VERSION 5.8 ;
BUSBITCHARS "[]" ;
DIVIDERCHAR "/" ;
UNITS
    DATABASE MICRONS 1000 ;
END UNITS

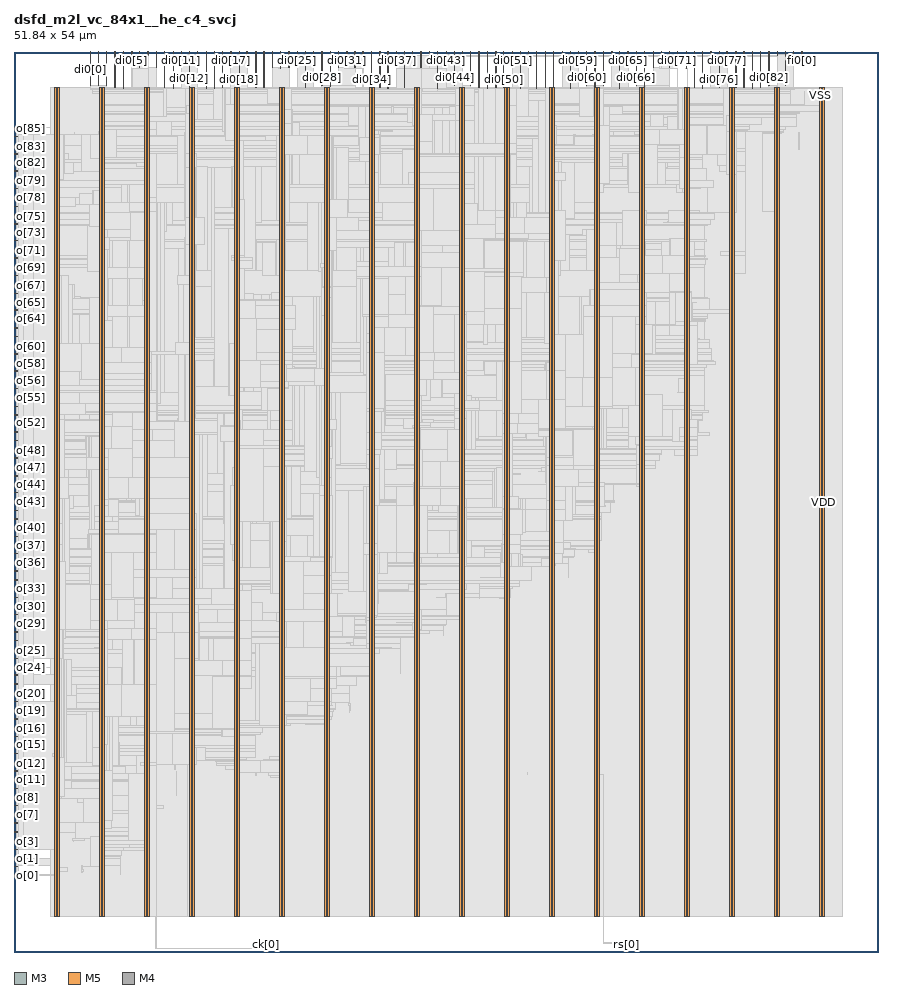
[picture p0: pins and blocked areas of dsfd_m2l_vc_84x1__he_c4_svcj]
MACRO dsfd_m2l_vc_84x1__he_c4_svcj
  FOREIGN dsfd_m2l_vc_84x1__he_c4_svcj 0 0 ;
  CLASS BLOCK ;
  SIZE 51.84 BY 54 ;
  PIN ck[0]
    DIRECTION INPUT ;
    USE SIGNAL ;
    PORT
      LAYER M3 ;
        RECT  15.12 0 15.138 0.144 ;
    END
    PORT
      LAYER M3 ;
        RECT  15.12 0.108 15.138 0.221 ;
    END
  END ck[0]
  PIN di0[0]
    DIRECTION INPUT ;
    USE SIGNAL ;
    PORT
      LAYER M3 ;
        RECT  4.572 53.856 4.59 54 ;
    END
    PORT
      LAYER M3 ;
        RECT  4.572 52.013 4.59 53.868 ;
    END
  END di0[0]
  PIN di0[10]
    DIRECTION INPUT ;
    USE SIGNAL ;
    PORT
      LAYER M3 ;
        RECT  9.54 53.856 9.558 54 ;
    END
    PORT
      LAYER M3 ;
        RECT  9.54 51.821 9.558 53.868 ;
    END
  END di0[10]
  PIN di0[11]
    DIRECTION INPUT ;
    USE SIGNAL ;
    PORT
      LAYER M5 ;
        RECT  10.032 53.808 10.056 54 ;
    END
  END di0[11]
  PIN di0[12]
    DIRECTION INPUT ;
    USE SIGNAL ;
    PORT
      LAYER M3 ;
        RECT  10.512 53.856 10.53 54 ;
    END
    PORT
      LAYER M3 ;
        RECT  10.512 51.935 10.53 53.868 ;
    END
  END di0[12]
  PIN di0[13]
    DIRECTION INPUT ;
    USE SIGNAL ;
    PORT
      LAYER M5 ;
        RECT  10.992 53.808 11.016 54 ;
    END
  END di0[13]
  PIN di0[14]
    DIRECTION INPUT ;
    USE SIGNAL ;
    PORT
      LAYER M3 ;
        RECT  11.52 53.856 11.538 54 ;
    END
    PORT
      LAYER M3 ;
        RECT  11.52 51.821 11.538 53.868 ;
    END
  END di0[14]
  PIN di0[15]
    DIRECTION INPUT ;
    USE SIGNAL ;
    PORT
      LAYER M5 ;
        RECT  12 53.808 12.024 54 ;
    END
    PORT
      LAYER M5 ;
        RECT  12 51.781 12.024 53.84 ;
    END
  END di0[15]
  PIN di0[16]
    DIRECTION INPUT ;
    USE SIGNAL ;
    PORT
      LAYER M3 ;
        RECT  12.492 53.856 12.51 54 ;
    END
    PORT
      LAYER M3 ;
        RECT  12.492 51.857 12.51 53.868 ;
    END
  END di0[16]
  PIN di0[17]
    DIRECTION INPUT ;
    USE SIGNAL ;
    PORT
      LAYER M5 ;
        RECT  13.008 53.808 13.032 54 ;
    END
  END di0[17]
  PIN di0[18]
    DIRECTION INPUT ;
    USE SIGNAL ;
    PORT
      LAYER M3 ;
        RECT  13.5 53.856 13.518 54 ;
    END
    PORT
      LAYER M3 ;
        RECT  13.5 51.869 13.518 53.868 ;
    END
  END di0[18]
  PIN di0[19]
    DIRECTION INPUT ;
    USE SIGNAL ;
    PORT
      LAYER M5 ;
        RECT  13.968 53.808 13.992 54 ;
    END
  END di0[19]
  PIN di0[1]
    DIRECTION INPUT ;
    USE SIGNAL ;
    PORT
      LAYER M5 ;
        RECT  5.04 53.808 5.064 54 ;
    END
    PORT
      LAYER M5 ;
        RECT  5.04 51.973 5.064 53.84 ;
    END
  END di0[1]
  PIN di0[20]
    DIRECTION INPUT ;
    USE SIGNAL ;
    PORT
      LAYER M3 ;
        RECT  14.508 53.856 14.526 54 ;
    END
    PORT
      LAYER M3 ;
        RECT  14.508 51.869 14.526 53.868 ;
    END
  END di0[20]
  PIN di0[21]
    DIRECTION INPUT ;
    USE SIGNAL ;
    PORT
      LAYER M5 ;
        RECT  14.976 53.808 15 54 ;
    END
    PORT
      LAYER M5 ;
        RECT  14.976 51.863 15 53.84 ;
    END
  END di0[21]
  PIN di0[22]
    DIRECTION INPUT ;
    USE SIGNAL ;
    PORT
      LAYER M3 ;
        RECT  15.48 53.856 15.498 54 ;
    END
    PORT
      LAYER M3 ;
        RECT  15.48 53.069 15.498 53.868 ;
    END
  END di0[22]
  PIN di0[23]
    DIRECTION INPUT ;
    USE SIGNAL ;
    PORT
      LAYER M5 ;
        RECT  15.984 53.808 16.008 54 ;
    END
    PORT
      LAYER M5 ;
        RECT  15.984 53.029 16.008 53.84 ;
    END
  END di0[23]
  PIN di0[24]
    DIRECTION INPUT ;
    USE SIGNAL ;
    PORT
      LAYER M3 ;
        RECT  16.488 53.856 16.506 54 ;
    END
    PORT
      LAYER M3 ;
        RECT  16.488 53.069 16.506 53.868 ;
    END
  END di0[24]
  PIN di0[25]
    DIRECTION INPUT ;
    USE SIGNAL ;
    PORT
      LAYER M5 ;
        RECT  16.992 53.808 17.016 54 ;
    END
  END di0[25]
  PIN di0[26]
    DIRECTION INPUT ;
    USE SIGNAL ;
    PORT
      LAYER M3 ;
        RECT  17.46 53.856 17.478 54 ;
    END
    PORT
      LAYER M3 ;
        RECT  17.46 51.869 17.478 53.868 ;
    END
  END di0[26]
  PIN di0[27]
    DIRECTION INPUT ;
    USE SIGNAL ;
    PORT
      LAYER M5 ;
        RECT  17.952 53.808 17.976 54 ;
    END
  END di0[27]
  PIN di0[28]
    DIRECTION INPUT ;
    USE SIGNAL ;
    PORT
      LAYER M3 ;
        RECT  18.468 53.856 18.486 54 ;
    END
    PORT
      LAYER M3 ;
        RECT  18.468 51.965 18.486 53.868 ;
    END
  END di0[28]
  PIN di0[29]
    DIRECTION INPUT ;
    USE SIGNAL ;
    PORT
      LAYER M5 ;
        RECT  18.96 53.808 18.984 54 ;
    END
    PORT
      LAYER M5 ;
        RECT  18.96 51.925 18.984 53.84 ;
    END
  END di0[29]
  PIN di0[2]
    DIRECTION INPUT ;
    USE SIGNAL ;
    PORT
      LAYER M3 ;
        RECT  5.544 53.856 5.562 54 ;
    END
    PORT
      LAYER M3 ;
        RECT  5.544 52.013 5.562 53.868 ;
    END
  END di0[2]
  PIN di0[30]
    DIRECTION INPUT ;
    USE SIGNAL ;
    PORT
      LAYER M3 ;
        RECT  19.44 53.856 19.458 54 ;
    END
    PORT
      LAYER M3 ;
        RECT  19.44 53.069 19.458 53.868 ;
    END
  END di0[30]
  PIN di0[31]
    DIRECTION INPUT ;
    USE SIGNAL ;
    PORT
      LAYER M5 ;
        RECT  19.968 53.808 19.992 54 ;
    END
  END di0[31]
  PIN di0[32]
    DIRECTION INPUT ;
    USE SIGNAL ;
    PORT
      LAYER M3 ;
        RECT  20.448 53.856 20.466 54 ;
    END
    PORT
      LAYER M3 ;
        RECT  20.448 53.069 20.466 53.868 ;
    END
  END di0[32]
  PIN di0[33]
    DIRECTION INPUT ;
    USE SIGNAL ;
    PORT
      LAYER M5 ;
        RECT  20.928 53.808 20.952 54 ;
    END
  END di0[33]
  PIN di0[34]
    DIRECTION INPUT ;
    USE SIGNAL ;
    PORT
      LAYER M3 ;
        RECT  21.456 53.856 21.474 54 ;
    END
    PORT
      LAYER M3 ;
        RECT  21.456 51.857 21.474 53.868 ;
    END
  END di0[34]
  PIN di0[35]
    DIRECTION INPUT ;
    USE SIGNAL ;
    PORT
      LAYER M5 ;
        RECT  21.936 53.808 21.96 54 ;
    END
    PORT
      LAYER M5 ;
        RECT  21.936 51.863 21.96 53.84 ;
    END
  END di0[35]
  PIN di0[36]
    DIRECTION INPUT ;
    USE SIGNAL ;
    PORT
      LAYER M3 ;
        RECT  22.428 53.856 22.446 54 ;
    END
    PORT
      LAYER M3 ;
        RECT  22.428 51.821 22.446 53.868 ;
    END
  END di0[36]
  PIN di0[37]
    DIRECTION INPUT ;
    USE SIGNAL ;
    PORT
      LAYER M5 ;
        RECT  22.944 53.808 22.968 54 ;
    END
  END di0[37]
  PIN di0[38]
    DIRECTION INPUT ;
    USE SIGNAL ;
    PORT
      LAYER M3 ;
        RECT  23.436 53.856 23.454 54 ;
    END
    PORT
      LAYER M3 ;
        RECT  23.436 51.857 23.454 53.868 ;
    END
  END di0[38]
  PIN di0[39]
    DIRECTION INPUT ;
    USE SIGNAL ;
    PORT
      LAYER M5 ;
        RECT  23.904 53.808 23.928 54 ;
    END
  END di0[39]
  PIN di0[3]
    DIRECTION INPUT ;
    USE SIGNAL ;
    PORT
      LAYER M5 ;
        RECT  6.048 53.808 6.072 54 ;
    END
    PORT
      LAYER M5 ;
        RECT  6.048 51.863 6.072 53.84 ;
    END
  END di0[3]
  PIN di0[40]
    DIRECTION INPUT ;
    USE SIGNAL ;
    PORT
      LAYER M3 ;
        RECT  24.408 53.856 24.426 54 ;
    END
    PORT
      LAYER M3 ;
        RECT  24.408 53.069 24.426 53.868 ;
    END
  END di0[40]
  PIN di0[41]
    DIRECTION INPUT ;
    USE SIGNAL ;
    PORT
      LAYER M5 ;
        RECT  24.912 53.808 24.936 54 ;
    END
    PORT
      LAYER M5 ;
        RECT  24.912 53.795 24.936 53.84 ;
    END
  END di0[41]
  PIN di0[42]
    DIRECTION INPUT ;
    USE SIGNAL ;
    PORT
      LAYER M3 ;
        RECT  25.416 53.856 25.434 54 ;
    END
    PORT
      LAYER M3 ;
        RECT  25.416 51.821 25.434 53.868 ;
    END
  END di0[42]
  PIN di0[43]
    DIRECTION INPUT ;
    USE SIGNAL ;
    PORT
      LAYER M5 ;
        RECT  25.92 53.808 25.944 54 ;
    END
  END di0[43]
  PIN di0[44]
    DIRECTION INPUT ;
    USE SIGNAL ;
    PORT
      LAYER M3 ;
        RECT  26.424 53.856 26.442 54 ;
    END
    PORT
      LAYER M3 ;
        RECT  26.424 51.965 26.442 53.868 ;
    END
  END di0[44]
  PIN di0[45]
    DIRECTION INPUT ;
    USE SIGNAL ;
    PORT
      LAYER M5 ;
        RECT  26.88 53.808 26.904 54 ;
    END
  END di0[45]
  PIN di0[46]
    DIRECTION INPUT ;
    USE SIGNAL ;
    PORT
      LAYER M3 ;
        RECT  27.396 53.856 27.414 54 ;
    END
    PORT
      LAYER M3 ;
        RECT  27.396 51.965 27.414 53.868 ;
    END
  END di0[46]
  PIN di0[47]
    DIRECTION INPUT ;
    USE SIGNAL ;
    PORT
      LAYER M5 ;
        RECT  27.888 53.808 27.912 54 ;
    END
    PORT
      LAYER M5 ;
        RECT  27.888 51.849 27.912 53.84 ;
    END
  END di0[47]
  PIN di0[48]
    DIRECTION INPUT ;
    USE SIGNAL ;
    PORT
      LAYER M3 ;
        RECT  28.404 53.856 28.422 54 ;
    END
    PORT
      LAYER M3 ;
        RECT  28.404 51.821 28.422 53.868 ;
    END
  END di0[48]
  PIN di0[49]
    DIRECTION INPUT ;
    USE SIGNAL ;
    PORT
      LAYER M5 ;
        RECT  28.896 53.808 28.92 54 ;
    END
    PORT
      LAYER M5 ;
        RECT  28.896 51.863 28.92 53.84 ;
    END
  END di0[49]
  PIN di0[4]
    DIRECTION INPUT ;
    USE SIGNAL ;
    PORT
      LAYER M3 ;
        RECT  6.552 53.856 6.57 54 ;
    END
    PORT
      LAYER M3 ;
        RECT  6.552 51.821 6.57 53.868 ;
    END
  END di0[4]
  PIN di0[50]
    DIRECTION INPUT ;
    USE SIGNAL ;
    PORT
      LAYER M3 ;
        RECT  29.376 53.856 29.394 54 ;
    END
    PORT
      LAYER M3 ;
        RECT  29.376 51.857 29.394 53.868 ;
    END
  END di0[50]
  PIN di0[51]
    DIRECTION INPUT ;
    USE SIGNAL ;
    PORT
      LAYER M5 ;
        RECT  29.904 53.808 29.928 54 ;
    END
  END di0[51]
  PIN di0[52]
    DIRECTION INPUT ;
    USE SIGNAL ;
    PORT
      LAYER M3 ;
        RECT  30.384 53.856 30.402 54 ;
    END
    PORT
      LAYER M3 ;
        RECT  30.384 51.821 30.402 53.868 ;
    END
  END di0[52]
  PIN di0[53]
    DIRECTION INPUT ;
    USE SIGNAL ;
    PORT
      LAYER M5 ;
        RECT  30.864 53.808 30.888 54 ;
    END
  END di0[53]
  PIN di0[54]
    DIRECTION INPUT ;
    USE SIGNAL ;
    PORT
      LAYER M3 ;
        RECT  31.356 53.856 31.374 54 ;
    END
    PORT
      LAYER M3 ;
        RECT  31.356 51.821 31.374 53.868 ;
    END
  END di0[54]
  PIN di0[55]
    DIRECTION INPUT ;
    USE SIGNAL ;
    PORT
      LAYER M5 ;
        RECT  31.872 53.808 31.896 54 ;
    END
    PORT
      LAYER M5 ;
        RECT  31.872 51.863 31.896 53.84 ;
    END
  END di0[55]
  PIN di0[56]
    DIRECTION INPUT ;
    USE SIGNAL ;
    PORT
      LAYER M3 ;
        RECT  32.364 53.856 32.382 54 ;
    END
    PORT
      LAYER M3 ;
        RECT  32.364 51.857 32.382 53.868 ;
    END
  END di0[56]
  PIN di0[57]
    DIRECTION INPUT ;
    USE SIGNAL ;
    PORT
      LAYER M5 ;
        RECT  32.88 53.808 32.904 54 ;
    END
  END di0[57]
  PIN di0[58]
    DIRECTION INPUT ;
    USE SIGNAL ;
    PORT
      LAYER M3 ;
        RECT  33.372 53.856 33.39 54 ;
    END
    PORT
      LAYER M3 ;
        RECT  33.372 51.821 33.39 53.868 ;
    END
  END di0[58]
  PIN di0[59]
    DIRECTION INPUT ;
    USE SIGNAL ;
    PORT
      LAYER M5 ;
        RECT  33.84 53.808 33.864 54 ;
    END
  END di0[59]
  PIN di0[5]
    DIRECTION INPUT ;
    USE SIGNAL ;
    PORT
      LAYER M5 ;
        RECT  7.056 53.808 7.08 54 ;
    END
  END di0[5]
  PIN di0[60]
    DIRECTION INPUT ;
    USE SIGNAL ;
    PORT
      LAYER M3 ;
        RECT  34.344 53.856 34.362 54 ;
    END
    PORT
      LAYER M3 ;
        RECT  34.344 52.013 34.362 53.868 ;
    END
  END di0[60]
  PIN di0[61]
    DIRECTION INPUT ;
    USE SIGNAL ;
    PORT
      LAYER M5 ;
        RECT  34.848 53.808 34.872 54 ;
    END
    PORT
      LAYER M5 ;
        RECT  34.848 51.863 34.872 53.84 ;
    END
  END di0[61]
  PIN di0[62]
    DIRECTION INPUT ;
    USE SIGNAL ;
    PORT
      LAYER M3 ;
        RECT  35.352 53.856 35.37 54 ;
    END
    PORT
      LAYER M3 ;
        RECT  35.352 52.013 35.37 53.868 ;
    END
  END di0[62]
  PIN di0[63]
    DIRECTION INPUT ;
    USE SIGNAL ;
    PORT
      LAYER M5 ;
        RECT  35.856 53.808 35.88 54 ;
    END
  END di0[63]
  PIN di0[64]
    DIRECTION INPUT ;
    USE SIGNAL ;
    PORT
      LAYER M3 ;
        RECT  36.324 53.856 36.342 54 ;
    END
    PORT
      LAYER M3 ;
        RECT  36.324 51.821 36.342 53.868 ;
    END
  END di0[64]
  PIN di0[65]
    DIRECTION INPUT ;
    USE SIGNAL ;
    PORT
      LAYER M5 ;
        RECT  36.816 53.808 36.84 54 ;
    END
  END di0[65]
  PIN di0[66]
    DIRECTION INPUT ;
    USE SIGNAL ;
    PORT
      LAYER M3 ;
        RECT  37.332 53.856 37.35 54 ;
    END
    PORT
      LAYER M3 ;
        RECT  37.332 51.965 37.35 53.868 ;
    END
  END di0[66]
  PIN di0[67]
    DIRECTION INPUT ;
    USE SIGNAL ;
    PORT
      LAYER M5 ;
        RECT  37.824 53.808 37.848 54 ;
    END
    PORT
      LAYER M5 ;
        RECT  37.824 51.925 37.848 53.84 ;
    END
  END di0[67]
  PIN di0[68]
    DIRECTION INPUT ;
    USE SIGNAL ;
    PORT
      LAYER M3 ;
        RECT  38.34 53.856 38.358 54 ;
    END
    PORT
      LAYER M3 ;
        RECT  38.34 53.069 38.358 53.868 ;
    END
  END di0[68]
  PIN di0[69]
    DIRECTION INPUT ;
    USE SIGNAL ;
    PORT
      LAYER M5 ;
        RECT  38.832 53.808 38.856 54 ;
    END
  END di0[69]
  PIN di0[6]
    DIRECTION INPUT ;
    USE SIGNAL ;
    PORT
      LAYER M3 ;
        RECT  7.524 53.856 7.542 54 ;
    END
    PORT
      LAYER M3 ;
        RECT  7.524 53.069 7.542 53.868 ;
    END
  END di0[6]
  PIN di0[70]
    DIRECTION INPUT ;
    USE SIGNAL ;
    PORT
      LAYER M3 ;
        RECT  39.312 53.856 39.33 54 ;
    END
    PORT
      LAYER M3 ;
        RECT  39.312 53.069 39.33 53.868 ;
    END
  END di0[70]
  PIN di0[71]
    DIRECTION INPUT ;
    USE SIGNAL ;
    PORT
      LAYER M5 ;
        RECT  39.792 53.808 39.816 54 ;
    END
  END di0[71]
  PIN di0[72]
    DIRECTION INPUT ;
    USE SIGNAL ;
    PORT
      LAYER M3 ;
        RECT  40.32 53.856 40.338 54 ;
    END
    PORT
      LAYER M3 ;
        RECT  40.32 53.015 40.338 53.868 ;
    END
  END di0[72]
  PIN di0[73]
    DIRECTION INPUT ;
    USE SIGNAL ;
    PORT
      LAYER M5 ;
        RECT  40.8 53.808 40.824 54 ;
    END
    PORT
      LAYER M5 ;
        RECT  40.8 51.863 40.824 53.84 ;
    END
  END di0[73]
  PIN di0[74]
    DIRECTION INPUT ;
    USE SIGNAL ;
    PORT
      LAYER M3 ;
        RECT  41.292 53.856 41.31 54 ;
    END
    PORT
      LAYER M3 ;
        RECT  41.292 51.821 41.31 53.868 ;
    END
  END di0[74]
  PIN di0[75]
    DIRECTION INPUT ;
    USE SIGNAL ;
    PORT
      LAYER M5 ;
        RECT  41.808 53.808 41.832 54 ;
    END
  END di0[75]
  PIN di0[76]
    DIRECTION INPUT ;
    USE SIGNAL ;
    PORT
      LAYER M3 ;
        RECT  42.3 53.856 42.318 54 ;
    END
    PORT
      LAYER M3 ;
        RECT  42.3 51.857 42.318 53.868 ;
    END
  END di0[76]
  PIN di0[77]
    DIRECTION INPUT ;
    USE SIGNAL ;
    PORT
      LAYER M5 ;
        RECT  42.768 53.808 42.792 54 ;
    END
  END di0[77]
  PIN di0[78]
    DIRECTION INPUT ;
    USE SIGNAL ;
    PORT
      LAYER M3 ;
        RECT  43.308 53.856 43.326 54 ;
    END
    PORT
      LAYER M3 ;
        RECT  43.308 51.857 43.326 53.868 ;
    END
  END di0[78]
  PIN di0[79]
    DIRECTION INPUT ;
    USE SIGNAL ;
    PORT
      LAYER M5 ;
        RECT  43.776 53.808 43.8 54 ;
    END
    PORT
      LAYER M5 ;
        RECT  43.776 51.863 43.8 53.84 ;
    END
  END di0[79]
  PIN di0[7]
    DIRECTION INPUT ;
    USE SIGNAL ;
    PORT
      LAYER M5 ;
        RECT  8.016 53.808 8.04 54 ;
    END
  END di0[7]
  PIN di0[80]
    DIRECTION INPUT ;
    USE SIGNAL ;
    PORT
      LAYER M3 ;
        RECT  44.28 53.856 44.298 54 ;
    END
    PORT
      LAYER M3 ;
        RECT  44.28 51.821 44.298 53.868 ;
    END
  END di0[80]
  PIN di0[81]
    DIRECTION INPUT ;
    USE SIGNAL ;
    PORT
      LAYER M5 ;
        RECT  44.784 53.808 44.808 54 ;
    END
    PORT
      LAYER M5 ;
        RECT  44.784 51.863 44.808 53.84 ;
    END
  END di0[81]
  PIN di0[82]
    DIRECTION INPUT ;
    USE SIGNAL ;
    PORT
      LAYER M3 ;
        RECT  45.288 53.856 45.306 54 ;
    END
    PORT
      LAYER M3 ;
        RECT  45.288 51.965 45.306 53.868 ;
    END
  END di0[82]
  PIN di0[83]
    DIRECTION INPUT ;
    USE SIGNAL ;
    PORT
      LAYER M5 ;
        RECT  45.792 53.808 45.816 54 ;
    END
  END di0[83]
  PIN di0[84]
    DIRECTION INPUT ;
    USE SIGNAL ;
    PORT
      LAYER M3 ;
        RECT  46.26 53.856 46.278 54 ;
    END
    PORT
      LAYER M3 ;
        RECT  46.26 51.965 46.278 53.868 ;
    END
  END di0[84]
  PIN di0[85]
    DIRECTION INPUT ;
    USE SIGNAL ;
    PORT
      LAYER M5 ;
        RECT  46.752 53.808 46.776 54 ;
    END
  END di0[85]
  PIN di0[8]
    DIRECTION INPUT ;
    USE SIGNAL ;
    PORT
      LAYER M3 ;
        RECT  8.532 53.856 8.55 54 ;
    END
    PORT
      LAYER M3 ;
        RECT  8.532 53.069 8.55 53.868 ;
    END
  END di0[8]
  PIN di0[9]
    DIRECTION INPUT ;
    USE SIGNAL ;
    PORT
      LAYER M5 ;
        RECT  9.024 53.808 9.048 54 ;
    END
    PORT
      LAYER M5 ;
        RECT  9.024 51.849 9.048 53.84 ;
    END
  END di0[9]
  PIN fi0[0]
    DIRECTION INPUT ;
    USE SIGNAL ;
    PORT
      LAYER M3 ;
        RECT  47.268 53.856 47.286 54 ;
    END
    PORT
      LAYER M3 ;
        RECT  47.268 53.755 47.286 53.868 ;
    END
  END fi0[0]
  PIN o[0]
    DIRECTION OUTPUT ;
    USE SIGNAL ;
    PORT
      LAYER M4 ;
        RECT  0 4.608 0.192 4.632 ;
    END
  END o[0]
  PIN o[10]
    DIRECTION OUTPUT ;
    USE SIGNAL ;
    PORT
      LAYER M4 ;
        RECT  0 9.792 0.192 9.816 ;
    END
  END o[10]
  PIN o[11]
    DIRECTION OUTPUT ;
    USE SIGNAL ;
    PORT
      LAYER M4 ;
        RECT  0 10.32 0.192 10.344 ;
    END
  END o[11]
  PIN o[12]
    DIRECTION OUTPUT ;
    USE SIGNAL ;
    PORT
      LAYER M4 ;
        RECT  0 10.848 0.192 10.872 ;
    END
  END o[12]
  PIN o[13]
    DIRECTION OUTPUT ;
    USE SIGNAL ;
    PORT
      LAYER M4 ;
        RECT  0 11.376 0.192 11.4 ;
    END
  END o[13]
  PIN o[14]
    DIRECTION OUTPUT ;
    USE SIGNAL ;
    PORT
      LAYER M4 ;
        RECT  0 11.904 0.192 11.928 ;
    END
  END o[14]
  PIN o[15]
    DIRECTION OUTPUT ;
    USE SIGNAL ;
    PORT
      LAYER M4 ;
        RECT  0 12.432 0.192 12.456 ;
    END
  END o[15]
  PIN o[16]
    DIRECTION OUTPUT ;
    USE SIGNAL ;
    PORT
      LAYER M4 ;
        RECT  0 12.912 0.192 12.936 ;
    END
  END o[16]
  PIN o[17]
    DIRECTION OUTPUT ;
    USE SIGNAL ;
    PORT
      LAYER M4 ;
        RECT  0 13.44 0.192 13.464 ;
    END
  END o[17]
  PIN o[18]
    DIRECTION OUTPUT ;
    USE SIGNAL ;
    PORT
      LAYER M4 ;
        RECT  0 13.968 0.192 13.992 ;
    END
  END o[18]
  PIN o[19]
    DIRECTION OUTPUT ;
    USE SIGNAL ;
    PORT
      LAYER M4 ;
        RECT  0 14.496 0.192 14.52 ;
    END
  END o[19]
  PIN o[1]
    DIRECTION OUTPUT ;
    USE SIGNAL ;
    PORT
      LAYER M4 ;
        RECT  0 5.136 0.192 5.16 ;
    END
  END o[1]
  PIN o[20]
    DIRECTION OUTPUT ;
    USE SIGNAL ;
    PORT
      LAYER M4 ;
        RECT  0 15.024 0.192 15.048 ;
    END
  END o[20]
  PIN o[21]
    DIRECTION OUTPUT ;
    USE SIGNAL ;
    PORT
      LAYER M4 ;
        RECT  0 15.552 0.192 15.576 ;
    END
  END o[21]
  PIN o[22]
    DIRECTION OUTPUT ;
    USE SIGNAL ;
    PORT
      LAYER M4 ;
        RECT  0 16.08 0.192 16.104 ;
    END
  END o[22]
  PIN o[23]
    DIRECTION OUTPUT ;
    USE SIGNAL ;
    PORT
      LAYER M4 ;
        RECT  0 16.608 0.192 16.632 ;
    END
  END o[23]
  PIN o[24]
    DIRECTION OUTPUT ;
    USE SIGNAL ;
    PORT
      LAYER M4 ;
        RECT  0 17.088 0.192 17.112 ;
    END
  END o[24]
  PIN o[25]
    DIRECTION OUTPUT ;
    USE SIGNAL ;
    PORT
      LAYER M4 ;
        RECT  0 17.616 0.192 17.64 ;
    END
  END o[25]
  PIN o[26]
    DIRECTION OUTPUT ;
    USE SIGNAL ;
    PORT
      LAYER M4 ;
        RECT  0 18.144 0.192 18.168 ;
    END
  END o[26]
  PIN o[27]
    DIRECTION OUTPUT ;
    USE SIGNAL ;
    PORT
      LAYER M4 ;
        RECT  0 18.672 0.192 18.696 ;
    END
  END o[27]
  PIN o[28]
    DIRECTION OUTPUT ;
    USE SIGNAL ;
    PORT
      LAYER M4 ;
        RECT  0 19.2 0.192 19.224 ;
    END
  END o[28]
  PIN o[29]
    DIRECTION OUTPUT ;
    USE SIGNAL ;
    PORT
      LAYER M4 ;
        RECT  0 19.728 0.192 19.752 ;
    END
  END o[29]
  PIN o[2]
    DIRECTION OUTPUT ;
    USE SIGNAL ;
    PORT
      LAYER M4 ;
        RECT  0 5.616 0.192 5.64 ;
    END
  END o[2]
  PIN o[30]
    DIRECTION OUTPUT ;
    USE SIGNAL ;
    PORT
      LAYER M4 ;
        RECT  0 20.256 0.192 20.28 ;
    END
  END o[30]
  PIN o[31]
    DIRECTION OUTPUT ;
    USE SIGNAL ;
    PORT
      LAYER M4 ;
        RECT  0 20.736 0.192 20.76 ;
    END
  END o[31]
  PIN o[32]
    DIRECTION OUTPUT ;
    USE SIGNAL ;
    PORT
      LAYER M4 ;
        RECT  0 21.264 0.192 21.288 ;
    END
  END o[32]
  PIN o[33]
    DIRECTION OUTPUT ;
    USE SIGNAL ;
    PORT
      LAYER M4 ;
        RECT  0 21.792 0.192 21.816 ;
    END
  END o[33]
  PIN o[34]
    DIRECTION OUTPUT ;
    USE SIGNAL ;
    PORT
      LAYER M4 ;
        RECT  0 22.32 0.192 22.344 ;
    END
  END o[34]
  PIN o[35]
    DIRECTION OUTPUT ;
    USE SIGNAL ;
    PORT
      LAYER M4 ;
        RECT  0 22.848 0.192 22.872 ;
    END
  END o[35]
  PIN o[36]
    DIRECTION OUTPUT ;
    USE SIGNAL ;
    PORT
      LAYER M4 ;
        RECT  0 23.376 0.192 23.4 ;
    END
  END o[36]
  PIN o[37]
    DIRECTION OUTPUT ;
    USE SIGNAL ;
    PORT
      LAYER M4 ;
        RECT  0 23.904 0.192 23.928 ;
    END
  END o[37]
  PIN o[38]
    DIRECTION OUTPUT ;
    USE SIGNAL ;
    PORT
      LAYER M4 ;
        RECT  0 24.384 0.192 24.408 ;
    END
  END o[38]
  PIN o[39]
    DIRECTION OUTPUT ;
    USE SIGNAL ;
    PORT
      LAYER M4 ;
        RECT  0 24.912 0.192 24.936 ;
    END
  END o[39]
  PIN o[3]
    DIRECTION OUTPUT ;
    USE SIGNAL ;
    PORT
      LAYER M4 ;
        RECT  0 6.144 0.192 6.168 ;
    END
  END o[3]
  PIN o[40]
    DIRECTION OUTPUT ;
    USE SIGNAL ;
    PORT
      LAYER M4 ;
        RECT  0 25.44 0.192 25.464 ;
    END
  END o[40]
  PIN o[41]
    DIRECTION OUTPUT ;
    USE SIGNAL ;
    PORT
      LAYER M4 ;
        RECT  0 25.968 0.192 25.992 ;
    END
  END o[41]
  PIN o[42]
    DIRECTION OUTPUT ;
    USE SIGNAL ;
    PORT
      LAYER M4 ;
        RECT  0 26.496 0.192 26.52 ;
    END
  END o[42]
  PIN o[43]
    DIRECTION OUTPUT ;
    USE SIGNAL ;
    PORT
      LAYER M4 ;
        RECT  0 27.024 0.192 27.048 ;
    END
  END o[43]
  PIN o[44]
    DIRECTION OUTPUT ;
    USE SIGNAL ;
    PORT
      LAYER M4 ;
        RECT  0 27.552 0.192 27.576 ;
    END
  END o[44]
  PIN o[45]
    DIRECTION OUTPUT ;
    USE SIGNAL ;
    PORT
      LAYER M4 ;
        RECT  0 28.032 0.192 28.056 ;
    END
  END o[45]
  PIN o[46]
    DIRECTION OUTPUT ;
    USE SIGNAL ;
    PORT
      LAYER M4 ;
        RECT  0 28.56 0.192 28.584 ;
    END
  END o[46]
  PIN o[47]
    DIRECTION OUTPUT ;
    USE SIGNAL ;
    PORT
      LAYER M4 ;
        RECT  0 29.088 0.192 29.112 ;
    END
  END o[47]
  PIN o[48]
    DIRECTION OUTPUT ;
    USE SIGNAL ;
    PORT
      LAYER M4 ;
        RECT  0 29.616 0.192 29.64 ;
    END
  END o[48]
  PIN o[49]
    DIRECTION OUTPUT ;
    USE SIGNAL ;
    PORT
      LAYER M4 ;
        RECT  0 30.144 0.192 30.168 ;
    END
  END o[49]
  PIN o[4]
    DIRECTION OUTPUT ;
    USE SIGNAL ;
    PORT
      LAYER M4 ;
        RECT  0 6.672 0.192 6.696 ;
    END
  END o[4]
  PIN o[50]
    DIRECTION OUTPUT ;
    USE SIGNAL ;
    PORT
      LAYER M4 ;
        RECT  0 30.672 0.192 30.696 ;
    END
  END o[50]
  PIN o[51]
    DIRECTION OUTPUT ;
    USE SIGNAL ;
    PORT
      LAYER M4 ;
        RECT  0 31.2 0.192 31.224 ;
    END
  END o[51]
  PIN o[52]
    DIRECTION OUTPUT ;
    USE SIGNAL ;
    PORT
      LAYER M4 ;
        RECT  0 31.728 0.192 31.752 ;
    END
  END o[52]
  PIN o[53]
    DIRECTION OUTPUT ;
    USE SIGNAL ;
    PORT
      LAYER M4 ;
        RECT  0 32.208 0.192 32.232 ;
    END
  END o[53]
  PIN o[54]
    DIRECTION OUTPUT ;
    USE SIGNAL ;
    PORT
      LAYER M4 ;
        RECT  0 32.736 0.192 32.76 ;
    END
  END o[54]
  PIN o[55]
    DIRECTION OUTPUT ;
    USE SIGNAL ;
    PORT
      LAYER M4 ;
        RECT  0 33.264 0.192 33.288 ;
    END
  END o[55]
  PIN o[56]
    DIRECTION OUTPUT ;
    USE SIGNAL ;
    PORT
      LAYER M4 ;
        RECT  0 33.792 0.192 33.816 ;
    END
  END o[56]
  PIN o[57]
    DIRECTION OUTPUT ;
    USE SIGNAL ;
    PORT
      LAYER M4 ;
        RECT  0 34.32 0.192 34.344 ;
    END
  END o[57]
  PIN o[58]
    DIRECTION OUTPUT ;
    USE SIGNAL ;
    PORT
      LAYER M4 ;
        RECT  0 34.848 0.192 34.872 ;
    END
  END o[58]
  PIN o[59]
    DIRECTION OUTPUT ;
    USE SIGNAL ;
    PORT
      LAYER M4 ;
        RECT  0 35.376 0.192 35.4 ;
    END
  END o[59]
  PIN o[5]
    DIRECTION OUTPUT ;
    USE SIGNAL ;
    PORT
      LAYER M4 ;
        RECT  0 7.2 0.192 7.224 ;
    END
  END o[5]
  PIN o[60]
    DIRECTION OUTPUT ;
    USE SIGNAL ;
    PORT
      LAYER M4 ;
        RECT  0 35.856 0.192 35.88 ;
    END
  END o[60]
  PIN o[61]
    DIRECTION OUTPUT ;
    USE SIGNAL ;
    PORT
      LAYER M4 ;
        RECT  0 36.384 0.192 36.408 ;
    END
  END o[61]
  PIN o[62]
    DIRECTION OUTPUT ;
    USE SIGNAL ;
    PORT
      LAYER M4 ;
        RECT  0 36.912 0.192 36.936 ;
    END
  END o[62]
  PIN o[63]
    DIRECTION OUTPUT ;
    USE SIGNAL ;
    PORT
      LAYER M4 ;
        RECT  0 37.44 0.192 37.464 ;
    END
  END o[63]
  PIN o[64]
    DIRECTION OUTPUT ;
    USE SIGNAL ;
    PORT
      LAYER M4 ;
        RECT  0 37.968 0.192 37.992 ;
    END
  END o[64]
  PIN o[65]
    DIRECTION OUTPUT ;
    USE SIGNAL ;
    PORT
      LAYER M4 ;
        RECT  0 38.496 0.192 38.52 ;
    END
  END o[65]
  PIN o[66]
    DIRECTION OUTPUT ;
    USE SIGNAL ;
    PORT
      LAYER M4 ;
        RECT  0 39.024 0.192 39.048 ;
    END
  END o[66]
  PIN o[67]
    DIRECTION OUTPUT ;
    USE SIGNAL ;
    PORT
      LAYER M4 ;
        RECT  0 39.504 0.192 39.528 ;
    END
  END o[67]
  PIN o[68]
    DIRECTION OUTPUT ;
    USE SIGNAL ;
    PORT
      LAYER M4 ;
        RECT  0 40.032 0.192 40.056 ;
    END
  END o[68]
  PIN o[69]
    DIRECTION OUTPUT ;
    USE SIGNAL ;
    PORT
      LAYER M4 ;
        RECT  0 40.56 0.192 40.584 ;
    END
  END o[69]
  PIN o[6]
    DIRECTION OUTPUT ;
    USE SIGNAL ;
    PORT
      LAYER M4 ;
        RECT  0 7.728 0.192 7.752 ;
    END
  END o[6]
  PIN o[70]
    DIRECTION OUTPUT ;
    USE SIGNAL ;
    PORT
      LAYER M4 ;
        RECT  0 41.088 0.192 41.112 ;
    END
  END o[70]
  PIN o[71]
    DIRECTION OUTPUT ;
    USE SIGNAL ;
    PORT
      LAYER M4 ;
        RECT  0 41.616 0.192 41.64 ;
    END
  END o[71]
  PIN o[72]
    DIRECTION OUTPUT ;
    USE SIGNAL ;
    PORT
      LAYER M4 ;
        RECT  0 42.144 0.192 42.168 ;
    END
  END o[72]
  PIN o[73]
    DIRECTION OUTPUT ;
    USE SIGNAL ;
    PORT
      LAYER M4 ;
        RECT  0 42.672 0.192 42.696 ;
    END
  END o[73]
  PIN o[74]
    DIRECTION OUTPUT ;
    USE SIGNAL ;
    PORT
      LAYER M4 ;
        RECT  0 43.152 0.192 43.176 ;
    END
  END o[74]
  PIN o[75]
    DIRECTION OUTPUT ;
    USE SIGNAL ;
    PORT
      LAYER M4 ;
        RECT  0 43.68 0.192 43.704 ;
    END
  END o[75]
  PIN o[76]
    DIRECTION OUTPUT ;
    USE SIGNAL ;
    PORT
      LAYER M4 ;
        RECT  0 44.208 0.192 44.232 ;
    END
  END o[76]
  PIN o[77]
    DIRECTION OUTPUT ;
    USE SIGNAL ;
    PORT
      LAYER M4 ;
        RECT  0 44.736 0.192 44.76 ;
    END
  END o[77]
  PIN o[78]
    DIRECTION OUTPUT ;
    USE SIGNAL ;
    PORT
      LAYER M4 ;
        RECT  0 45.264 0.192 45.288 ;
    END
  END o[78]
  PIN o[79]
    DIRECTION OUTPUT ;
    USE SIGNAL ;
    PORT
      LAYER M4 ;
        RECT  0 45.792 0.192 45.816 ;
    END
  END o[79]
  PIN o[7]
    DIRECTION OUTPUT ;
    USE SIGNAL ;
    PORT
      LAYER M4 ;
        RECT  0 8.256 0.192 8.28 ;
    END
  END o[7]
  PIN o[80]
    DIRECTION OUTPUT ;
    USE SIGNAL ;
    PORT
      LAYER M4 ;
        RECT  0 46.32 0.192 46.344 ;
    END
  END o[80]
  PIN o[81]
    DIRECTION OUTPUT ;
    USE SIGNAL ;
    PORT
      LAYER M4 ;
        RECT  0 46.848 0.192 46.872 ;
    END
  END o[81]
  PIN o[82]
    DIRECTION OUTPUT ;
    USE SIGNAL ;
    PORT
      LAYER M4 ;
        RECT  0 47.328 0.192 47.352 ;
    END
  END o[82]
  PIN o[83]
    DIRECTION OUTPUT ;
    USE SIGNAL ;
    PORT
      LAYER M4 ;
        RECT  0 47.856 0.192 47.88 ;
    END
  END o[83]
  PIN o[84]
    DIRECTION OUTPUT ;
    USE SIGNAL ;
    PORT
      LAYER M4 ;
        RECT  0 48.384 0.192 48.408 ;
    END
  END o[84]
  PIN o[85]
    DIRECTION OUTPUT ;
    USE SIGNAL ;
    PORT
      LAYER M4 ;
        RECT  0 48.912 0.192 48.936 ;
    END
  END o[85]
  PIN o[86]
    DIRECTION OUTPUT ;
    USE SIGNAL ;
    PORT
      LAYER M4 ;
        RECT  0 49.44 0.192 49.464 ;
    END
  END o[86]
  PIN o[8]
    DIRECTION OUTPUT ;
    USE SIGNAL ;
    PORT
      LAYER M4 ;
        RECT  0 8.784 0.192 8.808 ;
    END
  END o[8]
  PIN o[9]
    DIRECTION OUTPUT ;
    USE SIGNAL ;
    PORT
      LAYER M4 ;
        RECT  0 9.264 0.192 9.288 ;
    END
  END o[9]
  PIN rs[0]
    DIRECTION INPUT ;
    USE SIGNAL ;
    PORT
      LAYER M5 ;
        RECT  36.72 0 36.744 0.192 ;
    END
    PORT
      LAYER M5 ;
        RECT  36.72 0.144 36.744 0.563 ;
    END
  END rs[0]
  PIN VDD
    DIRECTION INOUT ;
    USE POWER ;
    PORT
      LAYER M5 ;
        RECT  48.492 2.151 48.612 51.849 ;
        RECT  45.792 2.151 45.912 51.849 ;
        RECT  43.092 2.151 43.212 51.849 ;
        RECT  40.392 2.151 40.512 51.849 ;
        RECT  37.692 2.151 37.812 51.849 ;
        RECT  34.992 2.151 35.112 51.849 ;
        RECT  32.292 2.151 32.412 51.849 ;
        RECT  29.592 2.151 29.712 51.849 ;
        RECT  26.892 2.151 27.012 51.849 ;
        RECT  24.192 2.151 24.312 51.849 ;
        RECT  21.492 2.151 21.612 51.849 ;
        RECT  18.792 2.151 18.912 51.849 ;
        RECT  16.092 2.151 16.212 51.849 ;
        RECT  13.392 2.151 13.512 51.849 ;
        RECT  10.692 2.151 10.812 51.849 ;
        RECT  7.992 2.151 8.112 51.849 ;
        RECT  5.292 2.151 5.412 51.849 ;
        RECT  2.592 2.151 2.712 51.849 ;
    END
  END VDD
  PIN VSS
    DIRECTION INOUT ;
    USE GROUND ;
    PORT
      LAYER M5 ;
        RECT  48.3 2.137 48.42 51.863 ;
        RECT  45.6 2.137 45.72 51.863 ;
        RECT  42.9 2.137 43.02 51.863 ;
        RECT  40.2 2.137 40.32 51.863 ;
        RECT  37.5 2.137 37.62 51.863 ;
        RECT  34.8 2.137 34.92 51.863 ;
        RECT  32.1 2.137 32.22 51.863 ;
        RECT  29.4 2.137 29.52 51.863 ;
        RECT  26.7 2.137 26.82 51.863 ;
        RECT  24 2.137 24.12 51.863 ;
        RECT  21.3 2.137 21.42 51.863 ;
        RECT  18.6 2.137 18.72 51.863 ;
        RECT  15.9 2.137 16.02 51.863 ;
        RECT  13.2 2.137 13.32 51.863 ;
        RECT  10.5 2.137 10.62 51.863 ;
        RECT  7.8 2.137 7.92 51.863 ;
        RECT  5.1 2.137 5.22 51.863 ;
        RECT  2.4 2.137 2.52 51.863 ;
    END
  END VSS
  # OT_OBS_CLOSED layer=M5 d_um=1.536 added=198
  OBS
    LAYER RVTN ;
     RECT  2.16 2.16 49.68 2.295 ;
     RECT  2.16 2.565 49.68 2.835 ;
     RECT  2.16 3.105 49.68 3.375 ;
     RECT  2.16 3.645 49.68 3.915 ;
     RECT  2.16 4.185 49.68 4.455 ;
     RECT  2.16 4.725 49.68 4.995 ;
     RECT  2.16 5.265 49.68 5.535 ;
     RECT  2.16 5.805 49.68 6.075 ;
     RECT  2.16 6.345 49.68 6.615 ;
     RECT  2.16 6.885 49.68 7.155 ;
     RECT  2.16 7.425 49.68 7.695 ;
     RECT  2.16 7.965 49.68 8.235 ;
     RECT  2.16 8.505 49.68 8.775 ;
     RECT  2.16 9.045 49.68 9.315 ;
     RECT  2.16 9.585 49.68 9.855 ;
     RECT  2.16 10.125 49.68 10.395 ;
     RECT  2.16 10.665 49.68 10.935 ;
     RECT  2.16 11.205 49.68 11.475 ;
     RECT  2.16 11.745 49.68 12.015 ;
     RECT  2.16 12.285 49.68 12.555 ;
     RECT  2.16 12.825 49.68 13.095 ;
     RECT  2.16 13.365 49.68 13.635 ;
     RECT  2.16 13.905 49.68 14.175 ;
     RECT  2.16 14.445 49.68 14.715 ;
     RECT  2.16 14.985 49.68 15.255 ;
     RECT  2.16 15.525 49.68 15.795 ;
     RECT  2.16 16.065 49.68 16.335 ;
     RECT  2.16 16.605 49.68 16.875 ;
     RECT  2.16 17.145 49.68 17.415 ;
     RECT  2.16 17.685 49.68 17.955 ;
     RECT  2.16 18.225 49.68 18.495 ;
     RECT  2.16 18.765 49.68 19.035 ;
     RECT  2.16 19.305 49.68 19.575 ;
     RECT  2.16 19.845 49.68 20.115 ;
     RECT  2.16 20.385 49.68 20.655 ;
     RECT  2.16 20.925 49.68 21.195 ;
     RECT  2.16 21.465 49.68 21.735 ;
     RECT  2.16 22.005 49.68 22.275 ;
     RECT  2.16 22.545 49.68 22.815 ;
     RECT  2.16 23.085 49.68 23.355 ;
     RECT  2.16 23.625 49.68 23.895 ;
     RECT  2.16 24.165 49.68 24.435 ;
     RECT  2.16 24.705 49.68 24.975 ;
     RECT  2.16 25.245 49.68 25.515 ;
     RECT  2.16 25.785 49.68 26.055 ;
     RECT  2.16 26.325 49.68 26.595 ;
     RECT  2.16 26.865 49.68 27.135 ;
     RECT  2.16 27.405 49.68 27.675 ;
     RECT  2.16 27.945 49.68 28.215 ;
     RECT  2.16 28.485 49.68 28.755 ;
     RECT  2.16 29.025 49.68 29.295 ;
     RECT  2.16 29.565 49.68 29.835 ;
     RECT  2.16 30.105 49.68 30.375 ;
     RECT  2.16 30.645 49.68 30.915 ;
     RECT  2.16 31.185 49.68 31.455 ;
     RECT  2.16 31.725 49.68 31.995 ;
     RECT  2.16 32.265 49.68 32.535 ;
     RECT  2.16 32.805 49.68 33.075 ;
     RECT  2.16 33.345 49.68 33.615 ;
     RECT  2.16 33.885 49.68 34.155 ;
     RECT  2.16 34.425 49.68 34.695 ;
     RECT  2.16 34.965 49.68 35.235 ;
     RECT  2.16 35.505 49.68 35.775 ;
     RECT  2.16 36.045 49.68 36.315 ;
     RECT  2.16 36.585 49.68 36.855 ;
     RECT  2.16 37.125 49.68 37.395 ;
     RECT  2.16 37.665 49.68 37.935 ;
     RECT  2.16 38.205 49.68 38.475 ;
     RECT  2.16 38.745 49.68 39.015 ;
     RECT  2.16 39.285 49.68 39.555 ;
     RECT  2.16 39.825 49.68 40.095 ;
     RECT  2.16 40.365 49.68 40.635 ;
     RECT  2.16 40.905 49.68 41.175 ;
     RECT  2.16 41.445 49.68 41.715 ;
     RECT  2.16 41.985 49.68 42.255 ;
     RECT  2.16 42.525 49.68 42.795 ;
     RECT  2.16 43.065 49.68 43.335 ;
     RECT  2.16 43.605 49.68 43.875 ;
     RECT  2.16 44.145 49.68 44.415 ;
     RECT  2.16 44.685 49.68 44.955 ;
     RECT  2.16 45.225 49.68 45.495 ;
     RECT  2.16 45.765 49.68 46.035 ;
     RECT  2.16 46.305 49.68 46.575 ;
     RECT  2.16 46.845 49.68 47.115 ;
     RECT  2.16 47.385 49.68 47.655 ;
     RECT  2.16 47.925 49.68 48.195 ;
     RECT  2.16 48.465 49.68 48.735 ;
     RECT  2.16 49.005 49.68 49.275 ;
     RECT  2.16 49.545 49.68 49.815 ;
     RECT  2.16 50.085 49.68 50.355 ;
     RECT  2.16 50.625 49.68 50.895 ;
     RECT  2.16 51.165 49.68 51.435 ;
     RECT  2.16 51.705 49.68 51.84 ;
    LAYER RVTP ;
     RECT  2.16 2.295 49.68 2.565 ;
     RECT  2.16 2.835 49.68 3.105 ;
     RECT  2.16 3.375 49.68 3.645 ;
     RECT  2.16 3.915 49.68 4.185 ;
     RECT  2.16 4.455 49.68 4.725 ;
     RECT  2.16 4.995 49.68 5.265 ;
     RECT  2.16 5.535 49.68 5.805 ;
     RECT  2.16 6.075 49.68 6.345 ;
     RECT  2.16 6.615 49.68 6.885 ;
     RECT  2.16 7.155 49.68 7.425 ;
     RECT  2.16 7.695 49.68 7.965 ;
     RECT  2.16 8.235 49.68 8.505 ;
     RECT  2.16 8.775 49.68 9.045 ;
     RECT  2.16 9.315 49.68 9.585 ;
     RECT  2.16 9.855 49.68 10.125 ;
     RECT  2.16 10.395 49.68 10.665 ;
     RECT  2.16 10.935 49.68 11.205 ;
     RECT  2.16 11.475 49.68 11.745 ;
     RECT  2.16 12.015 49.68 12.285 ;
     RECT  2.16 12.555 49.68 12.825 ;
     RECT  2.16 13.095 49.68 13.365 ;
     RECT  2.16 13.635 49.68 13.905 ;
     RECT  2.16 14.175 49.68 14.445 ;
     RECT  2.16 14.715 49.68 14.985 ;
     RECT  2.16 15.255 49.68 15.525 ;
     RECT  2.16 15.795 49.68 16.065 ;
     RECT  2.16 16.335 49.68 16.605 ;
     RECT  2.16 16.875 49.68 17.145 ;
     RECT  2.16 17.415 49.68 17.685 ;
     RECT  2.16 17.955 49.68 18.225 ;
     RECT  2.16 18.495 49.68 18.765 ;
     RECT  2.16 19.035 49.68 19.305 ;
     RECT  2.16 19.575 49.68 19.845 ;
     RECT  2.16 20.115 49.68 20.385 ;
     RECT  2.16 20.655 49.68 20.925 ;
     RECT  2.16 21.195 49.68 21.465 ;
     RECT  2.16 21.735 49.68 22.005 ;
     RECT  2.16 22.275 49.68 22.545 ;
     RECT  2.16 22.815 49.68 23.085 ;
     RECT  2.16 23.355 49.68 23.625 ;
     RECT  2.16 23.895 49.68 24.165 ;
     RECT  2.16 24.435 49.68 24.705 ;
     RECT  2.16 24.975 49.68 25.245 ;
     RECT  2.16 25.515 49.68 25.785 ;
     RECT  2.16 26.055 49.68 26.325 ;
     RECT  2.16 26.595 49.68 26.865 ;
     RECT  2.16 27.135 49.68 27.405 ;
     RECT  2.16 27.675 49.68 27.945 ;
     RECT  2.16 28.215 49.68 28.485 ;
     RECT  2.16 28.755 49.68 29.025 ;
     RECT  2.16 29.295 49.68 29.565 ;
     RECT  2.16 29.835 49.68 30.105 ;
     RECT  2.16 30.375 49.68 30.645 ;
     RECT  2.16 30.915 49.68 31.185 ;
     RECT  2.16 31.455 49.68 31.725 ;
     RECT  2.16 31.995 49.68 32.265 ;
     RECT  2.16 32.535 49.68 32.805 ;
     RECT  2.16 33.075 49.68 33.345 ;
     RECT  2.16 33.615 49.68 33.885 ;
     RECT  2.16 34.155 49.68 34.425 ;
     RECT  2.16 34.695 49.68 34.965 ;
     RECT  2.16 35.235 49.68 35.505 ;
     RECT  2.16 35.775 49.68 36.045 ;
     RECT  2.16 36.315 49.68 36.585 ;
     RECT  2.16 36.855 49.68 37.125 ;
     RECT  2.16 37.395 49.68 37.665 ;
     RECT  2.16 37.935 49.68 38.205 ;
     RECT  2.16 38.475 49.68 38.745 ;
     RECT  2.16 39.015 49.68 39.285 ;
     RECT  2.16 39.555 49.68 39.825 ;
     RECT  2.16 40.095 49.68 40.365 ;
     RECT  2.16 40.635 49.68 40.905 ;
     RECT  2.16 41.175 49.68 41.445 ;
     RECT  2.16 41.715 49.68 41.985 ;
     RECT  2.16 42.255 49.68 42.525 ;
     RECT  2.16 42.795 49.68 43.065 ;
     RECT  2.16 43.335 49.68 43.605 ;
     RECT  2.16 43.875 49.68 44.145 ;
     RECT  2.16 44.415 49.68 44.685 ;
     RECT  2.16 44.955 49.68 45.225 ;
     RECT  2.16 45.495 49.68 45.765 ;
     RECT  2.16 46.035 49.68 46.305 ;
     RECT  2.16 46.575 49.68 46.845 ;
     RECT  2.16 47.115 49.68 47.385 ;
     RECT  2.16 47.655 49.68 47.925 ;
     RECT  2.16 48.195 49.68 48.465 ;
     RECT  2.16 48.735 49.68 49.005 ;
     RECT  2.16 49.275 49.68 49.545 ;
     RECT  2.16 49.815 49.68 50.085 ;
     RECT  2.16 50.355 49.68 50.625 ;
     RECT  2.16 50.895 49.68 51.165 ;
     RECT  2.16 51.435 49.68 51.705 ;
    LAYER M1 ;
     RECT  2.16 2.151 49.68 51.849 ;
    LAYER M2 ;
     RECT  0.535 15.228 1.147 15.246 ;
     RECT  1.147 14.994 1.175 15.246 ;
     RECT  0.211 5.166 2.16 5.634 ;
     RECT  1.175 14.994 2.16 15.012 ;
     RECT  1.147 17.046 2.16 17.064 ;
     RECT  0.211 49.446 2.16 49.464 ;
     RECT  2.16 2.151 10.435 51.849 ;
     RECT  10.435 2.151 10.535 51.93 ;
     RECT  40.315 52.992 40.415 53.01 ;
     RECT  10.535 2.151 49.68 51.849 ;
    LAYER M3 ;
     RECT  35.352 0.523 35.37 2.143 ;
     RECT  2.415 2.143 2.505 2.413 ;
     RECT  5.115 2.143 5.205 2.413 ;
     RECT  7.815 2.143 7.905 2.413 ;
     RECT  10.515 2.143 10.605 2.413 ;
     RECT  13.215 2.143 13.305 2.413 ;
     RECT  15.915 2.143 16.005 2.413 ;
     RECT  18.615 2.143 18.705 2.413 ;
     RECT  21.315 2.143 21.405 2.413 ;
     RECT  24.015 2.143 24.105 2.413 ;
     RECT  26.715 2.143 26.805 2.413 ;
     RECT  29.415 2.143 29.505 2.413 ;
     RECT  32.115 2.143 32.205 2.413 ;
     RECT  37.515 2.143 37.605 2.413 ;
     RECT  40.215 2.143 40.305 2.413 ;
     RECT  42.915 2.143 43.005 2.413 ;
     RECT  45.615 2.143 45.705 2.413 ;
     RECT  48.315 2.143 48.405 2.413 ;
     RECT  2.415 2.413 2.697 4.603 ;
     RECT  2.304 4.603 2.697 4.649 ;
     RECT  2.415 4.649 2.697 4.801 ;
     RECT  4.068 4.765 4.086 4.801 ;
     RECT  4.068 4.801 4.158 4.955 ;
     RECT  2.415 4.801 3.222 5.099 ;
     RECT  5.115 2.413 5.397 5.161 ;
     RECT  6.372 4.621 6.39 5.161 ;
     RECT  4.068 4.955 4.086 5.165 ;
     RECT  5.115 5.161 6.39 5.611 ;
     RECT  0.216 5.131 0.234 5.648 ;
     RECT  5.112 5.611 6.39 5.729 ;
     RECT  5.115 5.729 6.39 5.809 ;
     RECT  5.115 5.809 6.426 6.091 ;
     RECT  5.115 6.091 6.858 6.241 ;
     RECT  5.115 6.241 6.93 6.421 ;
     RECT  7.815 2.413 8.097 6.421 ;
     RECT  5.115 6.421 8.097 6.683 ;
     RECT  3.564 6.655 3.582 6.691 ;
     RECT  3.492 6.691 4.23 6.809 ;
     RECT  3.708 6.809 4.23 6.845 ;
     RECT  5.115 6.683 6.858 6.907 ;
     RECT  3.96 6.845 4.23 6.961 ;
     RECT  5.076 6.907 6.858 6.961 ;
     RECT  3.96 6.961 6.858 7.259 ;
     RECT  3.96 7.259 4.158 7.385 ;
     RECT  5.076 7.259 6.858 7.469 ;
     RECT  5.115 7.469 6.858 8.311 ;
     RECT  7.815 6.683 8.097 8.311 ;
     RECT  5.115 8.311 6.894 8.465 ;
     RECT  7.815 8.311 8.226 8.581 ;
     RECT  7.815 8.581 8.982 8.807 ;
     RECT  4.14 7.385 4.158 8.941 ;
     RECT  3.816 8.941 4.158 9.211 ;
     RECT  7.815 8.807 8.442 9.239 ;
     RECT  2.415 5.099 2.697 9.349 ;
     RECT  2.415 9.349 3.078 9.355 ;
     RECT  3.816 9.211 4.23 9.355 ;
     RECT  2.415 9.355 4.23 9.389 ;
     RECT  3.42 9.389 4.23 9.391 ;
     RECT  5.115 8.465 6.858 9.391 ;
     RECT  3.42 9.391 6.858 10.201 ;
     RECT  2.415 9.389 2.697 10.291 ;
     RECT  3.42 10.201 6.894 10.291 ;
     RECT  2.415 10.291 6.894 10.349 ;
     RECT  7.815 9.239 8.226 10.435 ;
     RECT  15.915 2.413 16.197 10.471 ;
     RECT  7.815 10.435 8.334 10.589 ;
     RECT  15.408 10.471 16.197 10.597 ;
     RECT  34.815 2.143 35.37 10.625 ;
     RECT  3.42 10.349 6.894 10.699 ;
     RECT  7.815 10.589 8.226 10.699 ;
     RECT  3.42 10.699 8.226 10.739 ;
     RECT  30.78 10.633 30.798 10.769 ;
     RECT  14.508 10.597 14.526 10.829 ;
     RECT  2.415 10.349 2.697 10.831 ;
     RECT  15.264 10.597 16.197 10.831 ;
     RECT  9.72 9.391 9.738 10.859 ;
     RECT  13.215 2.413 13.497 10.939 ;
     RECT  2.304 10.831 2.697 11.131 ;
     RECT  3.42 10.739 6.678 11.131 ;
     RECT  12.672 10.939 13.497 11.173 ;
     RECT  12.528 11.173 13.497 11.209 ;
     RECT  10.515 2.413 10.797 11.227 ;
     RECT  12.168 11.209 13.497 11.281 ;
     RECT  12.168 11.281 13.554 11.407 ;
     RECT  2.304 11.131 6.678 11.408 ;
     RECT  10.515 11.227 10.962 11.467 ;
     RECT  12.06 11.407 13.554 11.467 ;
     RECT  2.415 11.408 6.678 11.479 ;
     RECT  7.56 10.739 8.226 11.479 ;
     RECT  10.515 11.467 13.554 11.515 ;
     RECT  14.94 10.831 16.197 11.543 ;
     RECT  10.515 11.515 13.59 11.551 ;
     RECT  10.515 11.551 13.95 11.641 ;
     RECT  15.3 11.543 16.197 11.741 ;
     RECT  2.415 11.479 8.226 11.749 ;
     RECT  9.648 10.975 9.666 11.983 ;
     RECT  2.415 11.749 8.802 12.055 ;
     RECT  9.612 11.983 9.702 12.055 ;
     RECT  10.515 11.641 14.49 12.055 ;
     RECT  2.415 12.055 9.702 12.217 ;
     RECT  10.476 12.055 14.49 12.217 ;
     RECT  2.415 12.217 14.49 12.361 ;
     RECT  2.304 12.361 14.49 13.019 ;
     RECT  2.415 13.019 14.49 13.063 ;
     RECT  2.415 13.063 14.778 13.171 ;
     RECT  2.415 13.171 14.886 13.441 ;
     RECT  15.915 11.741 16.197 13.441 ;
     RECT  0.216 13.339 0.234 13.469 ;
     RECT  2.415 13.441 16.197 13.567 ;
     RECT  2.415 13.567 16.362 13.603 ;
     RECT  18.615 2.413 18.897 13.675 ;
     RECT  2.415 13.603 16.578 13.711 ;
     RECT  17.46 13.675 18.897 13.711 ;
     RECT  2.415 13.711 18.897 13.945 ;
     RECT  1.152 13.867 1.17 13.997 ;
     RECT  2.415 13.945 19.026 14.143 ;
     RECT  2.415 14.143 19.134 14.413 ;
     RECT  20.124 14.341 20.142 14.485 ;
     RECT  2.415 14.413 19.17 14.521 ;
     RECT  2.415 14.521 19.314 14.639 ;
     RECT  20.124 14.485 20.214 14.791 ;
     RECT  20.052 14.791 20.214 14.909 ;
     RECT  3.744 14.639 19.314 14.953 ;
     RECT  20.052 14.909 20.142 14.953 ;
     RECT  1.152 14.989 1.17 15.223 ;
     RECT  0.54 15.223 1.17 15.251 ;
     RECT  2.415 14.639 2.862 15.493 ;
     RECT  3.744 14.953 20.142 15.493 ;
     RECT  0.54 15.251 0.558 15.581 ;
     RECT  2.415 15.493 20.142 15.961 ;
     RECT  2.415 15.961 20.574 16.501 ;
     RECT  21.315 2.413 21.597 16.501 ;
     RECT  2.415 16.501 21.597 16.915 ;
     RECT  2.415 16.915 21.654 17.069 ;
     RECT  1.152 17.041 1.17 17.117 ;
     RECT  2.415 17.069 12.33 17.923 ;
     RECT  13.068 17.069 21.597 17.923 ;
     RECT  2.415 17.923 21.942 18.235 ;
     RECT  23.184 16.681 23.202 18.235 ;
     RECT  2.415 18.235 23.202 18.499 ;
     RECT  2.304 18.499 23.202 18.841 ;
     RECT  24.015 2.413 24.297 18.841 ;
     RECT  2.304 18.841 24.297 18.959 ;
     RECT  20.448 18.959 24.297 19.111 ;
     RECT  2.304 18.959 19.71 19.229 ;
     RECT  20.448 19.111 24.93 19.291 ;
     RECT  25.776 19.003 25.794 19.291 ;
     RECT  20.448 19.291 25.794 19.579 ;
     RECT  20.448 19.579 25.902 19.651 ;
     RECT  0.216 19.627 0.234 19.757 ;
     RECT  20.448 19.651 25.974 19.921 ;
     RECT  26.715 2.413 26.997 19.921 ;
     RECT  2.415 19.229 19.71 20.149 ;
     RECT  20.448 19.921 26.997 20.149 ;
     RECT  2.415 20.149 26.997 20.155 ;
     RECT  2.376 20.155 26.997 20.309 ;
     RECT  29.415 2.413 29.697 21.235 ;
     RECT  27.9 21.235 27.918 21.271 ;
     RECT  29.124 21.235 29.697 21.271 ;
     RECT  2.415 20.309 26.997 21.739 ;
     RECT  27.9 21.271 29.79 21.811 ;
     RECT  27.9 21.811 29.898 21.901 ;
     RECT  2.415 21.739 27.126 22.081 ;
     RECT  27.9 21.901 30.33 22.081 ;
     RECT  2.415 22.081 30.33 22.279 ;
     RECT  2.415 22.279 31.05 23.131 ;
     RECT  2.415 23.131 31.374 23.161 ;
     RECT  32.115 2.413 32.397 23.161 ;
     RECT  2.415 23.161 32.49 23.323 ;
     RECT  33.264 22.441 33.282 23.323 ;
     RECT  34.815 10.625 35.097 23.629 ;
     RECT  2.415 23.323 33.282 23.665 ;
     RECT  2.415 23.665 33.57 23.701 ;
     RECT  34.815 23.629 35.154 23.971 ;
     RECT  2.415 23.701 33.642 24.133 ;
     RECT  34.452 23.971 35.154 24.133 ;
     RECT  2.415 24.133 35.154 24.331 ;
     RECT  2.304 24.331 35.154 24.413 ;
     RECT  2.415 24.413 35.154 24.673 ;
     RECT  2.415 24.673 35.226 25.951 ;
     RECT  2.304 25.951 35.226 25.997 ;
     RECT  2.415 25.997 35.226 26.131 ;
     RECT  2.415 26.131 35.262 26.365 ;
     RECT  0.216 26.491 0.234 26.621 ;
     RECT  2.415 26.365 35.802 26.941 ;
     RECT  2.415 26.941 36.054 27.019 ;
     RECT  2.304 27.019 36.054 27.095 ;
     RECT  37.515 2.413 37.797 27.949 ;
     RECT  2.304 27.095 35.982 28.021 ;
     RECT  37.332 27.949 37.797 28.021 ;
     RECT  2.304 28.021 37.797 29.029 ;
     RECT  2.304 29.029 38.466 29.219 ;
     RECT  2.415 29.219 38.466 29.461 ;
     RECT  40.215 2.413 40.497 29.803 ;
     RECT  2.415 29.461 38.754 29.839 ;
     RECT  2.415 29.839 38.826 29.911 ;
     RECT  2.415 29.911 38.862 30.145 ;
     RECT  39.6 29.803 41.022 30.145 ;
     RECT  2.415 30.145 41.022 30.331 ;
     RECT  2.34 30.331 41.022 30.667 ;
     RECT  2.304 30.667 41.022 30.749 ;
     RECT  2.415 30.749 41.022 30.991 ;
     RECT  2.415 30.991 41.742 31.145 ;
     RECT  2.415 31.145 41.094 31.915 ;
     RECT  2.415 31.915 41.31 32.161 ;
     RECT  2.304 32.161 41.31 32.237 ;
     RECT  2.376 32.237 41.31 32.341 ;
     RECT  2.376 32.341 41.67 32.495 ;
     RECT  2.376 32.495 41.454 32.765 ;
     RECT  0.216 33.643 0.234 33.821 ;
     RECT  2.415 32.765 41.454 34.591 ;
     RECT  2.304 34.591 41.454 34.877 ;
     RECT  2.415 34.877 41.454 35.041 ;
     RECT  2.415 35.041 41.562 35.239 ;
     RECT  2.415 35.239 42.066 35.429 ;
     RECT  2.415 35.429 41.958 35.465 ;
     RECT  0.216 35.371 0.234 35.501 ;
     RECT  2.415 35.465 41.85 35.851 ;
     RECT  2.304 35.851 41.85 35.969 ;
     RECT  2.412 35.969 41.85 36.239 ;
     RECT  2.412 36.239 41.742 36.545 ;
     RECT  2.415 36.545 41.742 36.779 ;
     RECT  2.415 36.779 41.418 37.819 ;
     RECT  2.415 37.819 41.454 37.867 ;
     RECT  2.415 37.867 41.49 37.963 ;
     RECT  2.412 37.963 41.49 38.011 ;
     RECT  2.412 38.011 41.598 38.129 ;
     RECT  2.415 38.129 41.598 38.281 ;
     RECT  42.915 2.413 43.197 38.281 ;
     RECT  2.415 38.281 43.197 38.543 ;
     RECT  2.415 38.543 41.742 39.209 ;
     RECT  2.415 39.209 41.634 39.245 ;
     RECT  42.915 38.543 43.197 40.711 ;
     RECT  2.415 39.245 41.418 41.071 ;
     RECT  2.304 41.071 41.418 41.251 ;
     RECT  2.304 41.251 41.49 41.521 ;
     RECT  2.304 41.521 41.634 41.639 ;
     RECT  42.915 40.711 43.866 41.791 ;
     RECT  2.304 41.639 41.454 41.792 ;
     RECT  42.408 41.791 43.866 42.053 ;
     RECT  2.304 41.792 41.418 42.179 ;
     RECT  2.415 42.179 41.418 42.601 ;
     RECT  1.152 42.571 1.17 42.701 ;
     RECT  2.415 42.601 41.526 42.755 ;
     RECT  0.216 43.147 0.234 43.325 ;
     RECT  2.415 42.755 41.418 43.609 ;
     RECT  2.415 43.609 41.598 43.645 ;
     RECT  2.415 43.645 41.814 43.675 ;
     RECT  2.304 43.675 41.814 43.951 ;
     RECT  2.304 43.951 42.03 44.339 ;
     RECT  2.415 44.339 41.886 44.375 ;
     RECT  45.615 2.413 45.897 44.419 ;
     RECT  2.415 44.375 41.598 45.841 ;
     RECT  2.415 45.841 41.958 46.265 ;
     RECT  42.915 42.053 43.866 46.849 ;
     RECT  2.415 46.265 41.562 47.039 ;
     RECT  42.336 46.849 43.866 47.191 ;
     RECT  2.415 47.039 41.31 47.579 ;
     RECT  4.032 47.579 41.31 47.651 ;
     RECT  2.415 47.579 3.294 47.885 ;
     RECT  6.156 47.651 41.31 48.001 ;
     RECT  42.192 47.191 43.866 48.001 ;
     RECT  6.156 48.001 43.866 48.191 ;
     RECT  4.032 47.651 5.397 48.361 ;
     RECT  6.156 48.191 41.274 48.389 ;
     RECT  3.456 48.361 5.397 48.413 ;
     RECT  3.564 48.413 5.397 48.659 ;
     RECT  6.156 48.389 41.238 48.929 ;
     RECT  4.464 48.659 5.397 48.965 ;
     RECT  9.288 48.929 41.238 49.001 ;
     RECT  1.116 48.907 1.134 49.037 ;
     RECT  3.564 48.659 3.618 49.037 ;
     RECT  44.928 44.419 45.897 49.081 ;
     RECT  44.928 49.081 46.026 49.195 ;
     RECT  3.6 49.037 3.618 49.199 ;
     RECT  47.088 48.163 47.106 49.199 ;
     RECT  5.04 48.965 5.397 49.235 ;
     RECT  44.928 49.195 46.17 49.235 ;
     RECT  42.012 48.191 43.866 49.315 ;
     RECT  5.115 49.235 5.397 49.351 ;
     RECT  6.156 48.929 8.55 49.351 ;
     RECT  9.468 49.001 41.238 49.351 ;
     RECT  42.012 49.315 44.01 49.351 ;
     RECT  45.615 49.235 46.17 49.351 ;
     RECT  0.216 49.432 0.234 49.469 ;
     RECT  9.468 49.351 44.154 49.505 ;
     RECT  45.615 49.351 46.314 49.549 ;
     RECT  38.952 49.505 44.154 49.621 ;
     RECT  5.115 49.351 8.55 49.855 ;
     RECT  9.468 49.505 38.214 49.855 ;
     RECT  38.952 49.621 44.838 50.089 ;
     RECT  45.615 49.549 46.926 50.089 ;
     RECT  5.115 49.855 38.214 50.251 ;
     RECT  38.952 50.089 46.926 50.251 ;
     RECT  5.115 50.251 46.926 50.287 ;
     RECT  5.115 50.287 47.106 50.431 ;
     RECT  48.315 2.413 48.597 50.431 ;
     RECT  5.115 50.431 48.597 50.819 ;
     RECT  5.115 50.819 47.43 50.855 ;
     RECT  5.115 50.855 46.566 51.511 ;
     RECT  2.415 47.885 2.697 51.587 ;
     RECT  48.315 50.819 48.597 51.587 ;
     RECT  4.68 51.511 46.566 51.629 ;
     RECT  47.412 50.855 47.43 51.629 ;
     RECT  4.68 51.629 24.498 51.745 ;
     RECT  25.416 51.629 46.566 51.745 ;
     RECT  4.572 51.745 24.498 51.821 ;
     RECT  25.416 51.745 46.818 51.821 ;
     RECT  2.415 51.587 2.505 51.857 ;
     RECT  10.44 51.821 10.605 51.857 ;
     RECT  12.492 51.821 14.526 51.857 ;
     RECT  21.315 51.821 21.474 51.857 ;
     RECT  23.436 51.821 24.498 51.857 ;
     RECT  29.376 51.821 29.505 51.857 ;
     RECT  32.115 51.821 32.382 51.857 ;
     RECT  42.3 51.821 43.326 51.857 ;
     RECT  48.315 51.587 48.405 51.857 ;
     RECT  13.5 51.857 14.526 51.869 ;
     RECT  15.48 51.821 17.478 51.869 ;
     RECT  37.332 51.821 40.41 51.869 ;
     RECT  10.44 51.857 10.53 51.935 ;
     RECT  18.468 51.821 20.466 51.965 ;
     RECT  26.424 51.821 27.414 51.965 ;
     RECT  37.332 51.869 39.33 51.965 ;
     RECT  45.288 51.821 46.278 51.965 ;
     RECT  4.572 51.821 5.562 52.013 ;
     RECT  34.344 51.821 35.37 52.013 ;
     RECT  40.392 51.869 40.41 52.987 ;
     RECT  40.32 52.987 40.41 53.015 ;
     RECT  7.524 51.821 8.55 53.069 ;
     RECT  15.48 51.869 16.506 53.069 ;
     RECT  19.44 51.965 20.466 53.069 ;
     RECT  24.408 51.857 24.498 53.069 ;
     RECT  38.34 51.965 39.33 53.069 ;
    LAYER M4 ;
     RECT  0.156 4.608 0.245 49.464 ;
     RECT  0.245 6.144 0.569 49.032 ;
     RECT  0.569 16.08 1.181 49.032 ;
     RECT  0.245 4.608 2.408 4.632 ;
     RECT  0.569 6.144 2.408 15.048 ;
     RECT  1.181 16.08 2.408 16.632 ;
     RECT  1.181 17.616 2.408 49.032 ;
     RECT  2.408 2.148 2.512 51.852 ;
     RECT  2.512 2.418 2.704 51.582 ;
     RECT  2.704 9.216 2.837 20.184 ;
     RECT  2.704 28.464 2.873 40.584 ;
     RECT  2.873 31.584 2.881 32.424 ;
     RECT  2.837 11.136 2.945 20.184 ;
     RECT  2.945 11.136 2.981 17.64 ;
     RECT  2.704 46.32 2.981 49.032 ;
     RECT  2.981 11.136 3.011 17.544 ;
     RECT  2.873 28.464 3.011 30.6 ;
     RECT  2.704 21.552 3.053 27.384 ;
     RECT  2.981 46.704 3.053 49.032 ;
     RECT  2.945 18.816 3.089 20.184 ;
     RECT  3.089 19.344 3.107 20.184 ;
     RECT  3.011 11.376 3.161 17.544 ;
     RECT  2.873 33.6 3.269 40.584 ;
     RECT  3.053 22.704 3.305 27.384 ;
     RECT  3.161 15.408 3.449 17.544 ;
     RECT  3.269 33.6 3.485 40.056 ;
     RECT  3.305 26.592 3.557 27.384 ;
     RECT  3.053 46.704 3.557 47.352 ;
     RECT  3.485 39.216 3.629 40.056 ;
     RECT  2.704 7.2 3.697 7.752 ;
     RECT  2.704 44.736 3.701 45.288 ;
     RECT  3.449 15.408 3.773 16.056 ;
     RECT  3.107 19.68 3.877 20.184 ;
     RECT  3.053 21.552 3.877 21.672 ;
     RECT  2.881 31.92 3.925 32.424 ;
     RECT  3.485 33.6 3.925 38.232 ;
     RECT  3.701 44.832 3.949 45.288 ;
     RECT  3.629 39.216 3.989 39.336 ;
     RECT  3.557 46.848 4.021 47.352 ;
     RECT  3.053 48.384 4.021 49.032 ;
     RECT  3.011 30.144 4.309 30.6 ;
     RECT  3.161 11.376 4.345 14.232 ;
     RECT  3.011 28.464 4.345 28.968 ;
     RECT  4.309 30.144 4.345 30.936 ;
     RECT  2.704 41.808 4.381 43.56 ;
     RECT  3.305 24.192 4.417 24.792 ;
     RECT  4.417 24.192 4.453 25.08 ;
     RECT  3.557 26.736 4.489 27.384 ;
     RECT  4.345 28.464 4.489 30.936 ;
     RECT  3.877 19.68 4.508 21.672 ;
     RECT  3.305 22.704 4.508 23.16 ;
     RECT  4.453 24.192 4.525 25.32 ;
     RECT  4.489 26.736 4.525 30.936 ;
     RECT  3.925 31.92 4.525 38.232 ;
     RECT  3.989 39.216 4.525 39.24 ;
     RECT  4.508 19.68 4.549 23.16 ;
     RECT  4.549 19.344 4.633 23.16 ;
     RECT  4.525 24.192 4.633 30.936 ;
     RECT  4.345 11.376 4.693 14.424 ;
     RECT  3.949 44.832 4.7 45.528 ;
     RECT  4.988 51.984 5.075 52.008 ;
     RECT  4.057 5.136 5.108 5.16 ;
     RECT  3.697 6.816 5.108 7.752 ;
     RECT  2.837 9.216 5.108 9.816 ;
     RECT  4.693 11.184 5.108 14.424 ;
     RECT  3.773 15.84 5.108 16.056 ;
     RECT  4.813 18.24 5.108 18.264 ;
     RECT  4.633 19.344 5.108 30.936 ;
     RECT  4.525 31.92 5.108 39.24 ;
     RECT  4.381 40.848 5.108 43.56 ;
     RECT  4.7 44.832 5.108 45.672 ;
     RECT  4.021 46.848 5.108 49.032 ;
     RECT  5.108 2.148 5.212 51.852 ;
     RECT  5.212 2.418 5.404 51.816 ;
     RECT  5.404 9.792 5.555 14.808 ;
     RECT  5.404 18.144 5.555 43.368 ;
     RECT  5.555 28.416 5.603 43.368 ;
     RECT  5.603 28.416 5.645 43.32 ;
     RECT  5.555 9.792 5.753 14.136 ;
     RECT  5.404 7.44 5.825 7.944 ;
     RECT  5.645 28.416 5.884 32.472 ;
     RECT  5.825 7.92 5.891 7.944 ;
     RECT  5.753 10.176 5.891 14.136 ;
     RECT  5.555 18.144 5.891 27.384 ;
     RECT  5.891 18.144 5.905 25.848 ;
     RECT  5.891 10.176 5.933 10.2 ;
     RECT  5.645 33.504 5.939 43.32 ;
     RECT  5.404 5.712 6.113 5.736 ;
     RECT  5.905 25.824 6.275 25.848 ;
     RECT  5.891 11.184 6.293 14.136 ;
     RECT  6.293 11.184 6.329 12.552 ;
     RECT  5.404 15.792 6.421 17.064 ;
     RECT  5.404 44.736 6.433 45 ;
     RECT  5.404 46.032 6.433 46.056 ;
     RECT  6.421 15.312 6.505 17.064 ;
     RECT  5.905 18.144 6.505 24.456 ;
     RECT  5.884 30.384 6.613 32.472 ;
     RECT  5.939 33.504 6.613 34.488 ;
     RECT  5.891 27.072 6.721 27.384 ;
     RECT  5.884 28.416 6.721 29.352 ;
     RECT  5.939 35.664 6.793 43.32 ;
     RECT  6.433 44.736 6.793 46.056 ;
     RECT  6.613 30.384 6.949 34.488 ;
     RECT  6.793 35.664 6.949 46.056 ;
     RECT  6.293 13.584 6.973 14.136 ;
     RECT  6.721 27.072 7.052 29.352 ;
     RECT  6.505 15.312 7.141 24.456 ;
     RECT  7.052 27.072 7.261 29.4 ;
     RECT  6.973 13.584 7.333 14.232 ;
     RECT  7.141 15.312 7.333 25.128 ;
     RECT  6.329 11.184 7.369 11.784 ;
     RECT  5.404 47.328 7.369 47.352 ;
     RECT  7.261 26.208 7.549 29.4 ;
     RECT  6.577 6.096 7.808 6.264 ;
     RECT  7.369 10.704 7.808 11.784 ;
     RECT  7.333 13.584 7.808 25.128 ;
     RECT  7.549 26.112 7.808 29.4 ;
     RECT  6.949 30.384 7.808 46.056 ;
     RECT  7.369 47.136 7.808 47.352 ;
     RECT  5.404 49.536 7.808 49.56 ;
     RECT  5.404 51.792 7.808 51.816 ;
     RECT  7.808 2.148 7.912 51.852 ;
     RECT  7.945 53.04 8.051 53.064 ;
     RECT  7.912 2.418 8.104 51.582 ;
     RECT  8.104 16.896 8.201 17.112 ;
     RECT  8.104 10.704 8.237 11.88 ;
     RECT  8.104 6.096 8.243 6.12 ;
     RECT  8.104 8.448 8.243 8.472 ;
     RECT  8.237 10.704 8.243 11.688 ;
     RECT  8.104 19.536 8.345 23.16 ;
     RECT  8.104 24.192 8.531 47.88 ;
     RECT  8.531 24.192 8.633 45 ;
     RECT  8.633 32.88 8.777 45 ;
     RECT  8.104 50.16 8.972 51.582 ;
     RECT  8.777 33.552 9.029 45 ;
     RECT  8.345 19.776 9.097 23.16 ;
     RECT  8.633 24.192 9.097 31.8 ;
     RECT  9.029 43.248 9.137 45 ;
     RECT  8.972 50.16 9.137 51.816 ;
     RECT  8.104 13.104 9.277 15.816 ;
     RECT  8.201 17.088 9.277 17.112 ;
     RECT  9.097 19.776 9.389 31.8 ;
     RECT  8.104 18.144 9.493 18.552 ;
     RECT  9.389 19.776 9.493 29.592 ;
     RECT  9.137 43.68 9.497 45 ;
     RECT  9.277 13.104 9.529 17.112 ;
     RECT  9.529 12.24 9.745 17.112 ;
     RECT  9.389 30.672 9.781 31.8 ;
     RECT  8.531 46.032 9.781 47.88 ;
     RECT  8.104 48.96 9.781 48.984 ;
     RECT  9.781 30.672 9.853 32.04 ;
     RECT  9.853 30.672 9.889 32.472 ;
     RECT  9.029 33.552 9.889 42.216 ;
     RECT  9.745 12.24 9.997 17.16 ;
     RECT  9.493 18.144 9.997 29.592 ;
     RECT  9.889 30.672 10.213 42.216 ;
     RECT  9.497 43.872 10.213 45 ;
     RECT  9.781 46.032 10.213 48.984 ;
     RECT  10.213 43.872 10.22 48.984 ;
     RECT  9.137 50.688 10.261 51.816 ;
     RECT  10.261 50.304 10.349 51.816 ;
     RECT  9.997 12.24 10.357 29.592 ;
     RECT  10.213 30.672 10.357 42.888 ;
     RECT  10.357 12.24 10.465 42.888 ;
     RECT  10.22 43.872 10.465 49.176 ;
     RECT  8.243 11.232 10.508 11.256 ;
     RECT  10.465 12.24 10.508 49.176 ;
     RECT  10.349 50.16 10.508 51.816 ;
     RECT  10.508 2.148 10.612 51.852 ;
     RECT  10.612 2.418 10.804 51.816 ;
     RECT  10.804 32.016 10.829 47.976 ;
     RECT  10.829 32.016 10.865 35.496 ;
     RECT  10.829 36.864 10.901 47.88 ;
     RECT  10.901 40.896 10.931 47.88 ;
     RECT  10.804 11.232 10.973 12.264 ;
     RECT  10.804 48.96 10.973 48.984 ;
     RECT  10.804 49.968 11.027 51.816 ;
     RECT  10.804 13.344 11.117 31.032 ;
     RECT  11.117 19.776 11.333 31.032 ;
     RECT  10.973 11.472 11.477 12.264 ;
     RECT  11.333 26.112 11.585 31.032 ;
     RECT  10.931 40.896 11.621 47.112 ;
     RECT  11.117 13.344 11.657 18.792 ;
     RECT  10.901 36.864 11.869 39.912 ;
     RECT  11.621 40.896 11.869 47.064 ;
     RECT  10.865 33.936 11.977 35.496 ;
     RECT  11.657 14.784 11.98 18.792 ;
     RECT  11.027 49.968 11.989 50.856 ;
     RECT  11.977 33.936 12.049 35.544 ;
     RECT  11.869 36.864 12.049 47.064 ;
     RECT  12.049 33.936 12.053 47.064 ;
     RECT  11.585 28.704 12.229 31.032 ;
     RECT  10.865 32.016 12.229 32.328 ;
     RECT  11.657 13.344 12.469 13.416 ;
     RECT  11.989 49.968 12.481 51.816 ;
     RECT  11.585 26.112 12.553 27.624 ;
     RECT  12.229 28.704 12.553 32.328 ;
     RECT  11.333 19.776 12.589 23.208 ;
     RECT  11.333 24.192 12.589 24.504 ;
     RECT  12.553 26.112 12.589 32.328 ;
     RECT  12.589 19.776 12.625 24.504 ;
     RECT  12.589 25.728 12.625 32.328 ;
     RECT  12.481 49.2 12.625 51.816 ;
     RECT  12.625 49.008 12.661 51.816 ;
     RECT  12.469 12.912 12.733 13.416 ;
     RECT  12.053 33.936 12.86 43.416 ;
     RECT  12.053 44.688 13.057 47.064 ;
     RECT  13.057 44.688 13.129 47.16 ;
     RECT  11.477 11.472 13.208 11.496 ;
     RECT  12.733 12.912 13.208 14.232 ;
     RECT  11.98 15.312 13.208 18.792 ;
     RECT  12.625 19.776 13.208 32.328 ;
     RECT  12.86 33.408 13.208 43.416 ;
     RECT  13.129 44.64 13.208 47.16 ;
     RECT  12.661 48.672 13.208 51.816 ;
     RECT  13.208 2.148 13.312 51.852 ;
     RECT  13.312 2.418 13.504 51.852 ;
     RECT  13.504 19.776 13.709 22.056 ;
     RECT  13.504 23.088 13.709 32.52 ;
     RECT  13.504 33.6 13.745 39.816 ;
     RECT  13.745 33.648 13.817 39.816 ;
     RECT  13.504 51.84 13.849 51.852 ;
     RECT  13.849 51.84 14.003 51.864 ;
     RECT  13.709 23.088 14.177 31.176 ;
     RECT  13.504 17.952 14.243 18.792 ;
     RECT  13.709 19.92 14.243 22.056 ;
     RECT  14.177 25.728 14.291 31.176 ;
     RECT  13.817 33.648 14.393 39.528 ;
     RECT  13.504 40.896 14.465 47.16 ;
     RECT  13.504 11.472 14.497 11.496 ;
     RECT  13.504 13.872 14.497 16.536 ;
     RECT  14.243 17.952 14.497 18.504 ;
     RECT  14.291 25.728 14.537 29.352 ;
     RECT  14.465 40.896 14.537 42.744 ;
     RECT  14.497 13.872 14.713 18.504 ;
     RECT  14.497 10.8 14.819 11.496 ;
     RECT  13.709 32.496 14.821 32.52 ;
     RECT  14.393 33.648 14.821 39.48 ;
     RECT  14.465 43.776 14.861 47.16 ;
     RECT  14.537 40.896 14.929 42.552 ;
     RECT  14.243 19.92 14.933 20.952 ;
     RECT  14.291 30.384 14.965 31.176 ;
     RECT  13.504 48.672 15.073 48.936 ;
     RECT  8.485 0.192 15.149 0.216 ;
     RECT  14.965 51.792 15.217 51.816 ;
     RECT  14.177 23.088 15.325 24.696 ;
     RECT  14.537 25.728 15.325 28.152 ;
     RECT  14.965 30.384 15.349 31.368 ;
     RECT  14.821 32.496 15.349 39.48 ;
     RECT  14.243 21.936 15.361 22.056 ;
     RECT  15.361 21.504 15.397 22.056 ;
     RECT  15.325 23.088 15.397 28.152 ;
     RECT  15.349 30.384 15.445 39.48 ;
     RECT  15.397 21.504 15.505 28.152 ;
     RECT  14.537 29.28 15.505 29.352 ;
     RECT  14.929 40.56 15.685 42.552 ;
     RECT  14.933 19.92 15.721 20.376 ;
     RECT  15.685 40.56 15.757 42.6 ;
     RECT  14.861 43.872 15.757 47.16 ;
     RECT  15.073 48.672 15.757 48.984 ;
     RECT  14.819 11.472 15.908 11.496 ;
     RECT  14.713 13.584 15.908 18.504 ;
     RECT  15.721 19.824 15.908 20.376 ;
     RECT  15.505 21.504 15.908 29.352 ;
     RECT  15.445 30.384 15.908 39.576 ;
     RECT  15.757 40.56 15.908 42.744 ;
     RECT  15.757 43.872 15.908 48.984 ;
     RECT  15.217 50.928 15.908 51.816 ;
     RECT  15.908 2.148 16.012 51.852 ;
     RECT  15.865 53.04 16.019 53.064 ;
     RECT  16.012 2.418 16.204 51.582 ;
     RECT  16.204 40.896 16.265 51.582 ;
     RECT  16.265 40.896 16.301 50.808 ;
     RECT  16.204 13.584 16.355 29.112 ;
     RECT  16.301 43.776 16.553 50.808 ;
     RECT  16.355 14.112 16.595 24.984 ;
     RECT  16.355 26.016 16.661 29.112 ;
     RECT  16.553 46.032 16.661 50.808 ;
     RECT  16.661 46.032 16.684 50.52 ;
     RECT  16.204 30.384 16.733 39.336 ;
     RECT  16.733 30.384 16.805 35.112 ;
     RECT  16.981 51.84 17.065 51.864 ;
     RECT  16.805 30.384 17.129 35.064 ;
     RECT  16.684 46.032 17.129 49.752 ;
     RECT  16.661 26.208 17.165 29.112 ;
     RECT  16.595 14.112 17.345 19.848 ;
     RECT  17.165 28.8 17.413 29.112 ;
     RECT  17.129 30.384 17.413 35.016 ;
     RECT  17.345 16.944 17.629 19.848 ;
     RECT  16.595 20.928 17.629 24.984 ;
     RECT  16.301 40.896 17.629 42.6 ;
     RECT  16.553 43.776 17.629 45 ;
     RECT  17.629 16.944 17.633 24.984 ;
     RECT  16.733 36.336 17.953 39.336 ;
     RECT  17.633 19.104 17.989 24.984 ;
     RECT  17.165 26.208 17.989 27.48 ;
     RECT  17.413 28.8 18.169 35.016 ;
     RECT  17.953 36 18.169 39.336 ;
     RECT  17.629 40.896 18.277 45 ;
     RECT  17.989 19.104 18.325 27.48 ;
     RECT  18.169 28.464 18.325 39.336 ;
     RECT  18.325 19.104 18.449 39.336 ;
     RECT  18.277 40.848 18.449 45 ;
     RECT  17.345 14.112 18.608 15.864 ;
     RECT  17.633 16.944 18.608 17.688 ;
     RECT  18.449 19.104 18.608 45 ;
     RECT  17.129 46.032 18.608 47.88 ;
     RECT  17.129 48.96 18.608 48.984 ;
     RECT  17.989 50.304 18.608 50.328 ;
     RECT  17.845 51.792 18.608 51.816 ;
     RECT  18.608 2.148 18.712 51.852 ;
     RECT  18.712 2.418 18.904 51.852 ;
     RECT  18.908 51.936 18.995 51.96 ;
     RECT  18.904 22.56 19.043 33.576 ;
     RECT  18.904 34.8 19.073 48.984 ;
     RECT  18.904 14.784 19.109 14.808 ;
     RECT  19.073 36.576 19.109 48.984 ;
     RECT  19.109 40.896 19.145 48.984 ;
     RECT  19.043 22.8 19.289 33.576 ;
     RECT  18.904 15.84 19.331 17.112 ;
     RECT  19.145 40.896 19.331 48.264 ;
     RECT  18.904 20.16 19.397 21.528 ;
     RECT  19.331 16.512 19.577 17.112 ;
     RECT  19.289 29.232 19.577 33.576 ;
     RECT  19.397 21.504 19.721 21.528 ;
     RECT  19.825 53.04 20.003 53.064 ;
     RECT  19.331 43.584 20.045 48.264 ;
     RECT  20.045 43.584 20.051 47.448 ;
     RECT  19.289 22.8 20.077 27.672 ;
     RECT  18.904 50.304 20.077 50.712 ;
     RECT  19.933 18.528 20.185 18.552 ;
     RECT  20.185 18.384 20.365 18.552 ;
     RECT  19.109 36.576 20.533 39.912 ;
     RECT  19.331 40.896 20.533 42.264 ;
     RECT  20.051 43.584 20.629 45 ;
     RECT  20.077 49.584 20.653 50.712 ;
     RECT  20.653 49.584 20.684 50.76 ;
     RECT  19.073 34.8 20.797 35.448 ;
     RECT  20.533 36.576 20.797 42.264 ;
     RECT  20.077 21.648 20.941 27.672 ;
     RECT  20.797 34.8 20.941 42.264 ;
     RECT  20.941 34.752 20.977 42.264 ;
     RECT  19.397 20.16 21.085 20.184 ;
     RECT  20.051 46.032 21.109 47.448 ;
     RECT  20.684 48.48 21.109 50.76 ;
     RECT  21.085 19.776 21.121 20.184 ;
     RECT  20.941 21.648 21.121 27.912 ;
     RECT  20.365 18.384 21.157 18.792 ;
     RECT  19.577 29.28 21.157 33.576 ;
     RECT  21.157 29.04 21.265 33.576 ;
     RECT  19.577 16.608 21.308 17.112 ;
     RECT  21.157 18.24 21.308 18.792 ;
     RECT  21.121 19.776 21.308 27.912 ;
     RECT  21.265 28.944 21.308 33.576 ;
     RECT  20.977 34.656 21.308 42.264 ;
     RECT  20.629 43.296 21.308 45 ;
     RECT  21.109 46.032 21.308 50.76 ;
     RECT  20.869 51.792 21.308 51.816 ;
     RECT  21.308 2.148 21.412 51.852 ;
     RECT  21.412 2.418 21.604 51.816 ;
     RECT  21.604 20.064 21.737 21.672 ;
     RECT  21.604 31.152 21.809 42.264 ;
     RECT  21.737 20.208 21.827 21.672 ;
     RECT  21.604 43.872 21.875 49.272 ;
     RECT  21.827 20.928 21.881 21.672 ;
     RECT  21.604 22.704 21.923 30.168 ;
     RECT  21.875 46.032 21.989 49.272 ;
     RECT  21.809 35.808 22.061 42.264 ;
     RECT  21.923 27.168 22.241 30.168 ;
     RECT  21.809 31.152 22.241 34.68 ;
     RECT  22.241 31.584 22.313 34.68 ;
     RECT  21.923 22.704 22.421 26.136 ;
     RECT  21.604 50.304 22.669 50.664 ;
     RECT  21.604 18.24 22.673 18.264 ;
     RECT  21.989 49.248 22.709 49.272 ;
     RECT  22.669 50.304 22.781 50.76 ;
     RECT  22.061 40.56 22.813 42.264 ;
     RECT  22.421 23.376 22.933 26.136 ;
     RECT  22.241 27.168 22.933 27.912 ;
     RECT  22.241 28.944 22.961 30.168 ;
     RECT  21.989 46.032 23.317 47.88 ;
     RECT  22.313 31.584 23.353 31.992 ;
     RECT  22.813 40.56 23.365 42.552 ;
     RECT  22.061 35.808 23.461 39.48 ;
     RECT  23.365 40.512 23.461 42.552 ;
     RECT  22.781 50.304 23.605 50.664 ;
     RECT  21.881 21.648 23.641 21.672 ;
     RECT  22.921 19.776 23.893 19.8 ;
     RECT  23.605 49.776 23.893 50.664 ;
     RECT  22.933 23.376 23.965 27.912 ;
     RECT  23.893 19.296 24.008 19.8 ;
     RECT  23.641 21.648 24.008 22.056 ;
     RECT  23.965 23.376 24.008 28.2 ;
     RECT  22.961 29.232 24.008 30.168 ;
     RECT  23.353 31.392 24.008 31.992 ;
     RECT  22.313 33.12 24.008 34.68 ;
     RECT  23.461 35.808 24.008 42.552 ;
     RECT  21.875 43.872 24.008 45 ;
     RECT  23.317 46.032 24.008 48.168 ;
     RECT  23.893 49.584 24.008 50.664 ;
     RECT  21.604 51.792 24.008 51.816 ;
     RECT  24.008 2.148 24.112 51.852 ;
     RECT  24.112 2.418 24.304 51.582 ;
     RECT  24.304 43.296 24.365 50.712 ;
     RECT  24.304 23.328 24.401 31.944 ;
     RECT  24.304 19.296 24.467 20.568 ;
     RECT  24.401 23.328 24.467 25.272 ;
     RECT  24.421 53.76 24.469 53.784 ;
     RECT  24.467 19.296 24.473 19.368 ;
     RECT  24.401 26.496 24.515 31.944 ;
     RECT  24.304 22.032 24.725 22.056 ;
     RECT  24.469 53.04 24.947 53.784 ;
     RECT  24.304 33.12 25.013 42.072 ;
     RECT  24.515 26.496 25.121 29.832 ;
     RECT  24.473 19.296 25.157 19.32 ;
     RECT  24.515 30.912 25.157 31.944 ;
     RECT  24.365 43.296 25.201 50.664 ;
     RECT  25.157 30.912 25.265 31.752 ;
     RECT  25.121 26.496 25.477 29.4 ;
     RECT  25.013 33.264 25.669 42.072 ;
     RECT  25.201 43.584 25.697 50.664 ;
     RECT  25.669 33.264 25.733 42.408 ;
     RECT  25.369 21.264 25.909 21.288 ;
     RECT  24.467 23.664 26.125 25.272 ;
     RECT  25.697 43.632 26.125 50.664 ;
     RECT  25.265 31.344 26.437 31.752 ;
     RECT  25.733 33.264 26.437 33.528 ;
     RECT  26.125 43.632 26.485 50.712 ;
     RECT  26.125 23.664 26.593 25.32 ;
     RECT  25.477 26.4 26.593 29.4 ;
     RECT  26.593 23.664 26.665 29.4 ;
     RECT  25.868 20.208 26.708 20.232 ;
     RECT  25.909 21.264 26.708 21.528 ;
     RECT  26.665 23.664 26.708 30.168 ;
     RECT  26.437 31.344 26.708 33.528 ;
     RECT  25.733 34.752 26.708 39.336 ;
     RECT  25.733 40.416 26.708 42.408 ;
     RECT  26.485 43.632 26.708 50.76 ;
     RECT  25.909 51.792 26.708 51.816 ;
     RECT  26.708 2.148 26.812 51.852 ;
     RECT  26.812 2.418 26.828 51.852 ;
     RECT  26.828 2.418 26.915 51.96 ;
     RECT  26.915 2.418 27.004 51.582 ;
     RECT  27.004 23.136 27.155 27.24 ;
     RECT  27.004 30.144 27.155 35.496 ;
     RECT  27.155 25.776 27.173 27.24 ;
     RECT  27.155 23.664 27.425 24.696 ;
     RECT  27.155 30.144 27.425 33.384 ;
     RECT  27.425 30.144 27.677 33.288 ;
     RECT  27.004 43.632 27.877 51.582 ;
     RECT  27.677 30.816 27.893 33.288 ;
     RECT  27.004 21.264 27.929 21.528 ;
     RECT  27.004 36.624 28.141 39.336 ;
     RECT  27.004 40.416 28.165 42.552 ;
     RECT  27.877 43.632 28.165 51.816 ;
     RECT  28.141 36.576 28.177 39.336 ;
     RECT  27.155 34.896 28.181 35.496 ;
     RECT  27.425 23.664 28.217 24.36 ;
     RECT  28.181 34.896 28.249 35.448 ;
     RECT  28.177 36.48 28.433 39.336 ;
     RECT  27.173 26.64 28.681 27.24 ;
     RECT  27.004 28.272 28.681 28.824 ;
     RECT  28.681 26.64 28.825 28.824 ;
     RECT  28.433 36.576 28.861 39.336 ;
     RECT  28.165 40.416 28.861 51.816 ;
     RECT  28.825 26.64 28.969 29.016 ;
     RECT  27.893 30.96 28.969 33.288 ;
     RECT  28.249 34.656 28.969 35.448 ;
     RECT  27.997 22.464 29.173 22.488 ;
     RECT  28.217 23.664 29.173 23.976 ;
     RECT  29.173 22.464 29.269 23.976 ;
     RECT  27.929 21.264 29.408 21.288 ;
     RECT  29.269 22.464 29.408 24.504 ;
     RECT  28.969 26.64 29.408 29.064 ;
     RECT  28.969 30.96 29.408 35.448 ;
     RECT  28.861 36.576 29.408 51.816 ;
     RECT  29.408 2.148 29.512 51.852 ;
     RECT  29.512 2.418 29.704 51.816 ;
     RECT  29.704 36.528 29.765 51.816 ;
     RECT  29.704 23.136 29.843 28.68 ;
     RECT  29.843 28.416 29.891 28.68 ;
     RECT  29.765 36.528 29.945 45 ;
     RECT  29.704 34.176 30.053 35.4 ;
     RECT  30.053 34.176 30.089 35.016 ;
     RECT  29.765 46.032 30.131 51.816 ;
     RECT  29.945 36.576 30.161 45 ;
     RECT  29.843 23.136 30.275 27.336 ;
     RECT  30.275 23.136 30.412 27.192 ;
     RECT  29.891 28.656 30.413 28.68 ;
     RECT  30.412 23.136 30.521 23.88 ;
     RECT  30.089 34.176 30.521 34.2 ;
     RECT  30.412 25.056 30.529 27.192 ;
     RECT  29.704 30.864 30.697 33.048 ;
     RECT  30.529 25.152 30.701 27.192 ;
     RECT  30.697 30.864 30.733 33.912 ;
     RECT  30.161 36.864 30.773 45 ;
     RECT  30.131 50.16 30.899 51.816 ;
     RECT  30.773 44.4 30.913 45 ;
     RECT  30.131 46.032 30.913 47.16 ;
     RECT  30.913 44.4 31.129 47.16 ;
     RECT  30.131 48.384 31.129 48.792 ;
     RECT  31.129 44.4 31.453 48.792 ;
     RECT  30.899 50.16 31.453 51.096 ;
     RECT  30.521 23.136 31.633 23.352 ;
     RECT  31.453 28.8 31.669 28.824 ;
     RECT  30.733 30.768 31.741 33.912 ;
     RECT  31.165 35.232 31.849 35.256 ;
     RECT  30.773 36.864 31.849 43.416 ;
     RECT  31.453 44.4 31.861 51.096 ;
     RECT  31.849 34.896 31.885 35.256 ;
     RECT  31.669 28.8 31.909 29.064 ;
     RECT  31.741 30.336 31.909 33.912 ;
     RECT  31.885 34.896 31.909 35.352 ;
     RECT  30.701 25.248 31.957 27.192 ;
     RECT  31.909 28.176 31.957 35.352 ;
     RECT  31.633 23.136 32.108 23.64 ;
     RECT  31.957 25.248 32.108 35.352 ;
     RECT  31.849 36.528 32.108 43.416 ;
     RECT  31.861 44.4 32.108 51.816 ;
     RECT  32.108 2.148 32.212 51.852 ;
     RECT  32.212 2.418 32.404 51.816 ;
     RECT  32.404 34.896 32.573 35.256 ;
     RECT  32.404 48.48 32.573 49.608 ;
     RECT  32.404 36.528 32.681 47.448 ;
     RECT  32.681 40.608 32.789 43.032 ;
     RECT  32.681 44.016 32.861 47.448 ;
     RECT  32.404 23.328 32.933 24.552 ;
     RECT  32.933 23.904 32.963 24.552 ;
     RECT  32.789 40.896 33.329 43.032 ;
     RECT  32.963 24.192 33.365 24.552 ;
     RECT  32.404 25.872 33.509 27.96 ;
     RECT  32.404 29.04 33.541 33.816 ;
     RECT  32.573 48.48 33.577 48.984 ;
     RECT  33.541 28.944 33.581 33.816 ;
     RECT  32.861 44.016 33.617 47.4 ;
     RECT  33.577 48.48 33.617 49.032 ;
     RECT  33.581 31.296 33.645 33.816 ;
     RECT  33.365 24.192 33.689 24.216 ;
     RECT  33.509 26.256 33.689 27.96 ;
     RECT  33.617 49.008 33.689 49.032 ;
     RECT  32.573 35.232 33.721 35.256 ;
     RECT  33.721 35.232 33.901 35.352 ;
     RECT  32.681 36.528 33.901 39.336 ;
     RECT  32.404 50.928 33.901 51.816 ;
     RECT  33.645 31.392 34.045 33.816 ;
     RECT  34.045 31.392 34.069 34.104 ;
     RECT  33.901 35.232 34.069 39.336 ;
     RECT  33.329 43.008 34.117 43.032 ;
     RECT  33.329 40.896 34.333 41.688 ;
     RECT  34.117 43.008 34.333 43.368 ;
     RECT  34.069 31.392 34.556 39.336 ;
     RECT  33.901 50.16 34.765 51.816 ;
     RECT  33.689 26.256 34.808 26.76 ;
     RECT  33.689 27.936 34.808 27.96 ;
     RECT  33.581 28.944 34.808 29.784 ;
     RECT  34.556 31.392 34.808 39.768 ;
     RECT  34.333 40.896 34.808 43.368 ;
     RECT  33.617 44.976 34.808 47.4 ;
     RECT  34.729 49.056 34.808 49.08 ;
     RECT  34.765 50.16 34.808 52.008 ;
     RECT  34.808 2.148 34.883 52.008 ;
     RECT  34.883 2.148 34.912 51.852 ;
     RECT  34.912 2.418 35.104 51.816 ;
     RECT  35.104 30.192 35.26 34.824 ;
     RECT  35.104 45.552 35.345 47.4 ;
     RECT  35.104 48.96 35.363 51.816 ;
     RECT  35.26 30.192 35.381 34.632 ;
     RECT  35.345 45.984 35.417 47.4 ;
     RECT  35.104 26.736 35.497 26.76 ;
     RECT  35.381 30.192 35.525 33.624 ;
     RECT  35.417 46.032 35.669 47.4 ;
     RECT  35.363 48.96 35.747 50.76 ;
     RECT  35.669 46.032 35.749 46.152 ;
     RECT  35.104 36.048 35.993 39.336 ;
     RECT  35.747 48.96 35.993 49.224 ;
     RECT  35.993 36.864 36.097 39.336 ;
     RECT  35.104 40.848 36.133 43.8 ;
     RECT  36.133 40.608 36.173 43.8 ;
     RECT  36.097 36.864 36.236 39.624 ;
     RECT  36.173 40.608 36.236 40.92 ;
     RECT  35.669 47.136 36.493 47.4 ;
     RECT  36.173 42.192 36.529 43.8 ;
     RECT  35.525 31.44 36.53 33.624 ;
     RECT  35.747 50.256 36.533 50.76 ;
     RECT  35.341 0.528 36.755 0.552 ;
     RECT  35.749 46.032 36.781 46.056 ;
     RECT  36.493 47.136 36.781 47.88 ;
     RECT  35.525 30.192 36.853 30.216 ;
     RECT  36.53 31.44 36.853 33.528 ;
     RECT  36.781 46.032 36.853 47.88 ;
     RECT  35.381 34.608 37.033 34.632 ;
     RECT  36.817 35.856 37.033 35.88 ;
     RECT  35.993 49.2 37.249 49.224 ;
     RECT  35.104 28.128 37.333 29.016 ;
     RECT  36.853 30.192 37.333 33.528 ;
     RECT  36.533 50.256 37.501 50.28 ;
     RECT  37.333 28.128 37.508 33.528 ;
     RECT  37.033 34.608 37.508 35.88 ;
     RECT  36.236 36.864 37.508 40.92 ;
     RECT  36.529 42.192 37.508 44.472 ;
     RECT  36.853 45.552 37.508 47.88 ;
     RECT  37.249 49.056 37.508 49.224 ;
     RECT  37.501 50.256 37.508 50.328 ;
     RECT  35.363 51.792 37.508 51.816 ;
     RECT  37.508 2.148 37.612 51.852 ;
     RECT  37.612 2.418 37.781 51.852 ;
     RECT  37.781 2.418 37.804 51.96 ;
     RECT  37.804 51.936 37.865 51.96 ;
     RECT  37.804 40.128 37.901 42.6 ;
     RECT  37.804 43.632 37.973 44.472 ;
     RECT  37.973 43.632 38.405 43.656 ;
     RECT  37.804 35.856 38.477 39.048 ;
     RECT  37.804 50.304 38.549 50.328 ;
     RECT  37.804 46.032 38.621 49.32 ;
     RECT  24.947 53.76 38.725 53.784 ;
     RECT  38.725 53.04 38.867 53.784 ;
     RECT  37.901 40.128 38.877 41.4 ;
     RECT  37.901 42.528 38.877 42.6 ;
     RECT  37.804 30.96 38.909 33.48 ;
     RECT  38.621 48.48 39.053 49.32 ;
     RECT  38.621 46.032 39.089 47.352 ;
     RECT  38.941 43.776 39.193 43.8 ;
     RECT  39.053 48.672 39.193 49.32 ;
     RECT  39.089 47.088 39.233 47.352 ;
     RECT  39.193 43.776 39.265 43.848 ;
     RECT  38.477 37.008 39.301 39.048 ;
     RECT  38.877 40.128 39.301 42.6 ;
     RECT  39.301 37.008 39.349 42.6 ;
     RECT  38.909 30.96 39.481 32.568 ;
     RECT  39.089 46.032 39.733 46.056 ;
     RECT  39.193 48.672 39.805 50.136 ;
     RECT  39.769 51.84 39.805 51.864 ;
     RECT  39.805 48.672 39.853 51.864 ;
     RECT  39.836 33.552 39.877 33.576 ;
     RECT  39.233 47.136 39.925 47.352 ;
     RECT  39.925 47.136 40.093 47.64 ;
     RECT  39.853 48.672 40.093 51.852 ;
     RECT  39.481 30.624 40.208 32.568 ;
     RECT  39.877 33.552 40.208 34.392 ;
     RECT  38.477 35.856 40.208 35.88 ;
     RECT  39.349 37.008 40.208 42.792 ;
     RECT  39.265 43.776 40.208 44.472 ;
     RECT  39.733 45.552 40.208 46.056 ;
     RECT  40.093 47.136 40.208 51.852 ;
     RECT  40.208 2.148 40.312 51.852 ;
     RECT  40.312 2.418 40.504 51.816 ;
     RECT  40.504 34.368 40.529 35.304 ;
     RECT  40.504 37.824 40.643 39.624 ;
     RECT  40.504 30.96 40.673 32.568 ;
     RECT  40.643 37.824 40.681 39 ;
     RECT  40.504 41.76 40.817 42.6 ;
     RECT  40.681 38.976 40.925 39 ;
     RECT  40.673 30.96 41.027 31.944 ;
     RECT  40.529 35.28 41.027 35.304 ;
     RECT  40.504 48.768 41.069 49.608 ;
     RECT  40.504 36.768 41.141 36.792 ;
     RECT  40.504 44.352 41.141 44.472 ;
     RECT  40.504 45.792 41.213 45.816 ;
     RECT  41.027 31.92 41.321 31.944 ;
     RECT  40.681 37.824 41.465 37.848 ;
     RECT  40.817 41.76 41.465 41.784 ;
     RECT  41.069 48.912 41.603 49.608 ;
     RECT  41.603 49.2 42.577 49.608 ;
     RECT  40.504 50.88 42.577 51.816 ;
     RECT  41.141 44.352 42.908 44.376 ;
     RECT  42.757 46.656 42.908 46.68 ;
     RECT  41.557 47.856 42.908 47.88 ;
     RECT  42.577 49.2 42.908 51.816 ;
     RECT  42.908 2.148 43.012 51.852 ;
     RECT  43.012 2.418 43.204 51.816 ;
     RECT  43.204 44.352 43.379 44.376 ;
     RECT  43.204 46.752 43.379 46.776 ;
     RECT  43.204 49.2 45.608 49.224 ;
     RECT  43.204 51.792 45.608 51.816 ;
     RECT  45.608 2.148 45.712 51.852 ;
     RECT  45.712 2.418 45.74 51.852 ;
     RECT  45.74 2.418 45.827 51.96 ;
     RECT  45.827 2.418 45.904 51.816 ;
     RECT  45.904 49.2 46.181 49.224 ;
     RECT  45.904 51.792 46.829 51.816 ;
     RECT  45.904 50.352 47.045 50.376 ;
     RECT  38.867 53.76 47.297 53.784 ;
     RECT  48.308 2.148 48.412 51.852 ;
     RECT  48.412 2.418 48.604 51.582 ;
    LAYER M5 ;
     RECT  8.496 0.181 8.52 2.137 ;
     RECT  2.4 2.137 2.52 2.151 ;
     RECT  5.1 2.137 5.22 2.151 ;
     RECT  10.5 2.137 10.62 2.151 ;
     RECT  13.2 2.137 13.32 2.151 ;
     RECT  15.9 2.137 16.02 2.151 ;
     RECT  18.6 2.137 18.72 2.151 ;
     RECT  21.3 2.137 21.42 2.151 ;
     RECT  24 2.137 24.12 2.151 ;
     RECT  26.7 2.137 26.82 2.151 ;
     RECT  29.4 2.137 29.52 2.151 ;
     RECT  32.1 2.137 32.22 2.151 ;
     RECT  34.8 2.137 34.92 2.151 ;
     RECT  37.5 2.137 37.62 2.151 ;
     RECT  40.2 2.137 40.32 2.151 ;
     RECT  42.9 2.137 43.02 2.151 ;
     RECT  45.6 2.137 45.72 2.151 ;
     RECT  48.3 2.137 48.42 2.151 ;
     RECT  5.1 2.151 5.412 5.125 ;
     RECT  4.56 5.125 5.412 6.947 ;
     RECT  5.1 6.947 5.412 7.909 ;
     RECT  2.4 2.151 2.712 9.349 ;
     RECT  5.1 7.909 5.88 10.883 ;
     RECT  5.1 10.883 5.412 11.173 ;
     RECT  7.8 2.137 8.52 11.173 ;
     RECT  7.584 11.173 8.52 11.363 ;
     RECT  14.784 10.789 14.808 11.507 ;
     RECT  2.4 9.349 3 11.651 ;
     RECT  2.4 11.651 2.712 11.749 ;
     RECT  2.304 11.749 2.712 11.939 ;
     RECT  4.704 11.173 5.412 12.275 ;
     RECT  5.1 12.275 5.412 12.469 ;
     RECT  13.2 2.151 13.512 12.901 ;
     RECT  7.8 11.363 8.52 13.093 ;
     RECT  9.504 11.221 9.528 13.093 ;
     RECT  10.5 2.151 10.812 13.093 ;
     RECT  7.8 13.093 10.812 13.235 ;
     RECT  9.6 13.235 10.812 13.333 ;
     RECT  12.48 12.901 13.512 13.379 ;
     RECT  9.6 13.333 11.448 13.381 ;
     RECT  15.9 2.151 16.212 13.573 ;
     RECT  5.1 12.469 5.592 14.101 ;
     RECT  18.6 2.151 18.912 14.197 ;
     RECT  15.9 13.573 16.344 14.243 ;
     RECT  9.6 13.381 11.928 14.339 ;
     RECT  17.616 14.197 18.912 14.773 ;
     RECT  17.616 14.773 19.032 15.059 ;
     RECT  13.2 13.379 13.512 15.781 ;
     RECT  17.808 15.059 19.032 15.829 ;
     RECT  5.1 14.101 6.456 16.067 ;
     RECT  7.8 13.235 8.52 16.069 ;
     RECT  15.9 14.243 16.212 16.405 ;
     RECT  17.808 15.829 19.32 16.405 ;
     RECT  11.904 14.339 11.928 16.501 ;
     RECT  13.2 15.781 14.232 16.501 ;
     RECT  15.9 16.405 19.32 16.547 ;
     RECT  11.904 16.501 14.232 16.595 ;
     RECT  12.528 16.595 14.232 17.507 ;
     RECT  2.4 11.939 2.712 17.605 ;
     RECT  9.6 14.339 10.812 17.605 ;
     RECT  21.3 2.151 21.612 18.229 ;
     RECT  15.9 16.547 18.912 18.275 ;
     RECT  21.168 18.229 21.612 18.517 ;
     RECT  7.248 16.069 8.52 18.757 ;
     RECT  13.2 17.507 14.232 18.803 ;
     RECT  9.6 17.605 11.064 19.141 ;
     RECT  2.4 17.605 2.904 19.333 ;
     RECT  5.1 16.067 5.592 19.333 ;
     RECT  24 2.151 24.312 19.333 ;
     RECT  7.056 18.757 8.52 19.427 ;
     RECT  15.9 18.275 16.344 19.813 ;
     RECT  17.376 18.275 18.912 19.813 ;
     RECT  21.12 18.517 21.612 19.907 ;
     RECT  4.56 19.333 5.592 19.909 ;
     RECT  13.2 18.803 13.512 19.909 ;
     RECT  21.168 19.907 21.612 20.099 ;
     RECT  21.3 20.099 21.612 20.197 ;
     RECT  26.7 2.151 27.012 20.197 ;
     RECT  7.248 19.427 8.52 20.389 ;
     RECT  9.504 19.141 11.064 20.389 ;
     RECT  12.192 19.765 12.216 20.579 ;
     RECT  15.9 19.813 18.912 20.579 ;
     RECT  24 19.333 24.456 20.579 ;
     RECT  7.248 20.389 11.064 20.869 ;
     RECT  4.56 19.909 6.216 21.155 ;
     RECT  7.248 20.869 11.832 21.203 ;
     RECT  7.248 21.203 8.52 21.253 ;
     RECT  17.376 20.579 18.912 21.493 ;
     RECT  25.92 20.197 27.012 21.539 ;
     RECT  13.2 19.909 14.232 21.683 ;
     RECT  9.504 21.203 11.832 21.827 ;
     RECT  4.56 21.155 5.832 22.067 ;
     RECT  7.152 21.253 8.52 22.453 ;
     RECT  9.504 21.827 10.92 22.453 ;
     RECT  29.4 2.151 29.712 22.453 ;
     RECT  17.376 21.493 19.032 22.595 ;
     RECT  7.152 22.453 10.92 22.979 ;
     RECT  26.7 21.539 27.012 23.125 ;
     RECT  24 20.579 24.312 23.317 ;
     RECT  29.184 22.453 29.712 23.363 ;
     RECT  2.4 19.333 3.096 23.411 ;
     RECT  17.376 22.595 18.912 23.411 ;
     RECT  13.2 21.683 13.512 23.509 ;
     RECT  17.808 23.411 18.912 23.653 ;
     RECT  24 23.317 24.456 23.653 ;
     RECT  17.808 23.653 19.08 23.747 ;
     RECT  21.3 20.197 21.816 23.845 ;
     RECT  24 23.653 25.416 23.891 ;
     RECT  29.4 23.363 29.712 23.893 ;
     RECT  32.1 2.151 32.412 23.893 ;
     RECT  5.1 22.067 5.832 23.941 ;
     RECT  7.152 22.979 8.52 23.941 ;
     RECT  2.4 23.411 2.712 24.469 ;
     RECT  13.104 23.509 13.512 24.469 ;
     RECT  29.4 23.893 30.36 24.469 ;
     RECT  20.976 23.845 21.816 24.515 ;
     RECT  32.1 23.893 32.952 24.563 ;
     RECT  15.9 20.579 16.212 24.613 ;
     RECT  5.1 23.941 8.52 25.045 ;
     RECT  29.28 24.469 30.36 25.045 ;
     RECT  4.464 25.045 8.52 25.139 ;
     RECT  4.464 25.139 6.264 25.331 ;
     RECT  7.8 25.139 8.52 25.333 ;
     RECT  9.6 22.979 10.92 25.333 ;
     RECT  2.4 24.469 2.904 25.715 ;
     RECT  15.9 24.613 16.344 25.813 ;
     RECT  4.8 25.331 6.264 25.859 ;
     RECT  32.1 24.563 32.412 25.861 ;
     RECT  4.8 25.859 5.88 26.147 ;
     RECT  7.8 25.333 10.92 26.291 ;
     RECT  32.1 25.861 33.096 26.533 ;
     RECT  29.28 25.045 30.504 26.579 ;
     RECT  29.28 26.579 30.36 26.627 ;
     RECT  26.7 23.125 27.144 26.675 ;
     RECT  34.8 2.151 35.112 26.725 ;
     RECT  4.8 26.147 5.64 26.771 ;
     RECT  22.944 23.941 22.968 26.771 ;
     RECT  21.3 24.515 21.816 26.773 ;
     RECT  24 23.891 24.792 26.773 ;
     RECT  31.92 26.533 33.096 27.107 ;
     RECT  5.1 26.771 5.64 27.157 ;
     RECT  2.4 25.715 2.712 27.205 ;
     RECT  7.8 26.291 10.812 27.205 ;
     RECT  29.28 26.627 30.264 27.347 ;
     RECT  18.336 23.747 19.08 27.395 ;
     RECT  24 26.773 25.608 27.781 ;
     RECT  26.7 26.675 27.012 27.781 ;
     RECT  24 27.781 27.012 27.923 ;
     RECT  34.8 26.725 35.448 27.925 ;
     RECT  13.008 24.469 13.512 27.971 ;
     RECT  18.336 27.395 18.912 27.971 ;
     RECT  37.5 2.151 37.812 28.117 ;
     RECT  33.888 27.925 35.448 28.163 ;
     RECT  6.864 27.205 10.812 28.451 ;
     RECT  18.6 27.971 18.912 28.453 ;
     RECT  2.4 27.205 3.288 28.499 ;
     RECT  5.1 27.157 5.688 28.933 ;
     RECT  33.888 28.163 35.112 28.933 ;
     RECT  21.3 26.773 21.912 29.029 ;
     RECT  13.104 27.971 13.512 29.075 ;
     RECT  14.976 25.813 16.344 29.123 ;
     RECT  31.92 27.107 32.412 29.173 ;
     RECT  33.552 28.933 35.112 29.173 ;
     RECT  31.92 29.173 35.112 29.219 ;
     RECT  37.344 28.117 37.812 29.267 ;
     RECT  25.584 27.923 27.012 29.411 ;
     RECT  18.6 28.453 19.032 29.605 ;
     RECT  31.92 29.219 33.576 29.651 ;
     RECT  4.368 28.933 5.688 29.699 ;
     RECT  7.104 28.451 10.812 29.699 ;
     RECT  32.1 29.651 33.576 29.795 ;
     RECT  21.168 29.029 21.912 29.845 ;
     RECT  21.168 29.845 21.96 30.133 ;
     RECT  24 27.923 24.504 30.179 ;
     RECT  5.1 29.699 5.688 30.181 ;
     RECT  13.2 29.075 13.512 30.181 ;
     RECT  14.976 29.123 16.212 30.181 ;
     RECT  18.6 29.605 19.08 30.323 ;
     RECT  37.5 29.267 37.812 30.373 ;
     RECT  13.2 30.181 16.212 30.419 ;
     RECT  37.344 30.373 37.812 30.469 ;
     RECT  13.2 30.419 13.512 30.613 ;
     RECT  40.2 2.151 40.512 30.613 ;
     RECT  7.104 29.699 8.112 30.709 ;
     RECT  14.976 30.419 16.212 30.709 ;
     RECT  32.1 29.795 32.412 30.949 ;
     RECT  37.296 30.469 37.812 30.949 ;
     RECT  39.936 30.613 40.512 30.949 ;
     RECT  29.28 27.347 29.88 31.093 ;
     RECT  21.168 30.133 22.056 31.189 ;
     RECT  31.488 30.949 32.412 31.285 ;
     RECT  33.504 29.795 33.576 31.285 ;
     RECT  31.488 31.285 33.576 31.331 ;
     RECT  18.6 30.323 19.032 31.333 ;
     RECT  7.104 30.709 8.328 31.379 ;
     RECT  14.976 30.709 16.728 31.379 ;
     RECT  26.016 29.411 27.012 31.379 ;
     RECT  24 30.179 24.408 31.381 ;
     RECT  34.8 29.219 35.112 31.381 ;
     RECT  31.488 31.331 33.528 31.427 ;
     RECT  39.936 30.949 41.016 31.475 ;
     RECT  23.904 31.381 24.408 31.477 ;
     RECT  34.704 31.381 35.112 31.523 ;
     RECT  5.1 30.181 5.832 31.525 ;
     RECT  12.384 30.613 13.512 31.525 ;
     RECT  12.384 31.525 13.608 31.571 ;
     RECT  23.904 31.477 24.984 31.619 ;
     RECT  29.28 31.093 30.216 31.717 ;
     RECT  24 31.619 24.984 31.763 ;
     RECT  9.6 29.699 10.812 31.811 ;
     RECT  13.2 31.571 13.608 31.907 ;
     RECT  15.36 31.379 16.728 31.907 ;
     RECT  2.4 28.499 3 31.955 ;
     RECT  18.6 31.333 19.368 31.955 ;
     RECT  40.2 31.475 41.016 31.955 ;
     RECT  26.448 31.379 27.012 32.005 ;
     RECT  5.1 31.525 5.928 32.245 ;
     RECT  29.28 31.717 30.264 32.293 ;
     RECT  4.272 32.245 5.928 32.389 ;
     RECT  7.104 31.379 8.112 32.389 ;
     RECT  4.272 32.389 8.112 32.437 ;
     RECT  21.12 31.189 22.056 32.437 ;
     RECT  15.36 31.907 16.212 32.485 ;
     RECT  26.448 32.005 27.144 32.485 ;
     RECT  21.12 32.437 22.152 32.581 ;
     RECT  34.8 31.523 35.112 32.581 ;
     RECT  26.448 32.485 27.912 32.627 ;
     RECT  34.8 32.581 35.88 32.725 ;
     RECT  36.864 30.949 37.812 32.771 ;
     RECT  4.272 32.437 8.52 32.917 ;
     RECT  26.7 32.627 27.912 33.107 ;
     RECT  31.488 31.427 33.096 33.155 ;
     RECT  13.2 31.907 13.512 33.397 ;
     RECT  24 31.763 24.456 33.397 ;
     RECT  40.2 31.955 40.512 33.541 ;
     RECT  2.4 31.955 2.712 33.589 ;
     RECT  3.936 32.917 8.52 33.589 ;
     RECT  2.4 33.589 8.52 33.683 ;
     RECT  15.216 32.485 16.212 33.829 ;
     RECT  15.216 33.829 16.488 33.877 ;
     RECT  18.6 31.955 18.912 33.973 ;
     RECT  2.4 33.683 8.112 34.019 ;
     RECT  14.784 33.877 16.488 34.259 ;
     RECT  3.936 34.019 8.112 34.355 ;
     RECT  24 33.397 24.744 34.357 ;
     RECT  39.888 33.541 40.512 34.403 ;
     RECT  34.08 32.725 35.88 34.451 ;
     RECT  5.1 34.355 8.112 34.693 ;
     RECT  26.7 33.107 27.144 34.741 ;
     RECT  3.936 34.355 4.056 34.835 ;
     RECT  31.92 33.155 33.096 34.883 ;
     RECT  18 33.973 18.912 35.027 ;
     RECT  37.296 32.771 37.812 35.077 ;
     RECT  14.784 34.259 16.344 35.269 ;
     RECT  40.2 34.403 40.512 35.269 ;
     RECT  5.1 34.693 8.232 35.363 ;
     RECT  29.28 32.293 30.456 35.459 ;
     RECT  14.784 35.269 16.68 35.461 ;
     RECT  24 34.357 25.176 35.461 ;
     RECT  10.272 31.811 10.812 35.845 ;
     RECT  37.056 35.077 37.812 35.845 ;
     RECT  37.056 35.845 38.28 35.891 ;
     RECT  14.544 35.461 16.68 35.987 ;
     RECT  21.12 32.581 22.2 35.987 ;
     RECT  24 35.461 25.224 35.987 ;
     RECT  7.8 35.363 8.232 36.035 ;
     RECT  5.1 35.363 6.456 36.275 ;
     RECT  4.032 34.835 4.056 36.515 ;
     RECT  12.912 33.397 13.512 36.515 ;
     RECT  9.696 35.845 10.812 36.563 ;
     RECT  21.12 35.987 21.612 36.563 ;
     RECT  32.1 34.883 33.096 37.043 ;
     RECT  21.168 36.563 21.612 37.091 ;
     RECT  14.544 35.987 16.212 37.333 ;
     RECT  21.3 37.091 21.612 37.477 ;
     RECT  40.2 35.269 41.016 37.573 ;
     RECT  37.296 35.891 38.28 37.667 ;
     RECT  39.696 37.573 41.016 37.859 ;
     RECT  5.1 36.275 5.928 37.907 ;
     RECT  14.544 37.333 16.872 38.005 ;
     RECT  7.8 36.035 8.112 38.149 ;
     RECT  21.3 37.477 22.488 38.149 ;
     RECT  34.176 34.451 35.88 38.149 ;
     RECT  37.296 37.667 37.944 38.149 ;
     RECT  18.432 35.027 18.912 38.195 ;
     RECT  20.928 38.149 22.488 38.243 ;
     RECT  26.448 34.741 27.144 38.243 ;
     RECT  26.7 38.243 27.144 38.435 ;
     RECT  28.224 37.669 28.248 38.581 ;
     RECT  29.4 35.459 30.456 38.581 ;
     RECT  24 35.987 25.176 38.725 ;
     RECT  14.496 38.005 16.872 38.771 ;
     RECT  24 38.725 25.656 38.771 ;
     RECT  6.816 38.149 8.112 38.819 ;
     RECT  34.176 38.149 37.944 38.819 ;
     RECT  7.68 38.819 8.112 39.107 ;
     RECT  13.2 36.515 13.512 39.109 ;
     RECT  14.496 38.771 16.212 39.109 ;
     RECT  13.2 39.109 16.212 39.155 ;
     RECT  18.6 38.195 18.912 39.253 ;
     RECT  15.456 39.155 16.212 39.587 ;
     RECT  32.1 37.043 32.412 39.589 ;
     RECT  39.696 37.859 40.632 39.589 ;
     RECT  39.312 39.589 40.632 39.635 ;
     RECT  34.608 38.819 37.812 39.779 ;
     RECT  18.6 39.253 19.032 39.877 ;
     RECT  18.48 39.877 19.032 39.923 ;
     RECT  10.176 36.563 10.812 40.021 ;
     RECT  34.8 39.779 37.812 40.163 ;
     RECT  7.8 39.107 8.112 40.405 ;
     RECT  20.928 38.243 22.44 40.405 ;
     RECT  31.968 39.589 32.412 40.499 ;
     RECT  20.544 40.405 22.44 40.501 ;
     RECT  24 38.771 24.456 40.501 ;
     RECT  28.224 38.581 30.456 40.549 ;
     RECT  9.792 40.021 10.812 40.595 ;
     RECT  37.392 40.163 37.812 40.643 ;
     RECT  39.312 39.635 40.512 40.693 ;
     RECT  28.224 40.549 30.552 40.787 ;
     RECT  28.224 40.787 28.248 40.835 ;
     RECT  13.2 39.155 13.8 40.981 ;
     RECT  6.816 40.405 8.112 41.075 ;
     RECT  25.632 38.771 25.656 41.075 ;
     RECT  18.48 39.923 18.912 41.077 ;
     RECT  20.544 40.501 24.456 41.123 ;
     RECT  18.384 41.077 18.912 41.315 ;
     RECT  20.544 41.123 22.44 41.411 ;
     RECT  13.2 40.981 14.28 41.461 ;
     RECT  32.1 40.499 32.412 41.509 ;
     RECT  13.056 41.461 14.28 41.651 ;
     RECT  34.8 40.163 36.312 41.651 ;
     RECT  13.056 41.651 13.8 41.795 ;
     RECT  38.928 40.693 40.512 41.795 ;
     RECT  18.6 41.315 18.912 42.085 ;
     RECT  5.1 37.907 5.592 42.133 ;
     RECT  36.144 41.651 36.312 42.229 ;
     RECT  21.3 41.411 22.44 42.275 ;
     RECT  36.144 42.229 36.408 42.371 ;
     RECT  25.68 41.941 25.704 42.419 ;
     RECT  10.272 40.595 10.812 42.421 ;
     RECT  29.4 40.787 30.552 42.613 ;
     RECT  7.8 41.075 8.112 42.709 ;
     RECT  28.176 40.981 28.2 42.709 ;
     RECT  29.4 42.613 30.792 42.709 ;
     RECT  28.176 42.709 30.792 42.757 ;
     RECT  28.176 42.757 30.888 42.803 ;
     RECT  39.36 41.795 40.512 42.803 ;
     RECT  5.1 42.133 5.736 42.851 ;
     RECT  28.896 42.803 30.888 43.139 ;
     RECT  21.3 42.275 21.612 43.285 ;
     RECT  24 41.123 24.456 43.285 ;
     RECT  5.1 42.851 5.592 43.379 ;
     RECT  5.1 43.379 5.412 43.525 ;
     RECT  26.7 38.435 27.012 43.621 ;
     RECT  20.64 43.285 21.612 43.861 ;
     RECT  18.6 42.085 19.32 44.053 ;
     RECT  20.64 43.861 22.104 44.053 ;
     RECT  10.272 42.421 11.4 44.099 ;
     RECT  18.6 44.053 22.104 44.099 ;
     RECT  28.896 43.139 30.648 44.099 ;
     RECT  6.96 42.709 8.112 44.341 ;
     RECT  42.9 2.151 43.212 44.341 ;
     RECT  20.016 44.099 22.104 44.387 ;
     RECT  6.912 44.341 8.112 44.437 ;
     RECT  28.896 44.099 29.712 44.483 ;
     RECT  32.1 41.509 33.096 44.483 ;
     RECT  4.512 43.525 5.412 44.867 ;
     RECT  26.7 43.621 27.816 44.915 ;
     RECT  6.912 44.437 8.52 44.963 ;
     RECT  21.3 44.387 22.104 44.963 ;
     RECT  13.2 41.795 13.8 45.155 ;
     RECT  20.016 44.387 20.04 45.155 ;
     RECT  7.8 44.963 8.52 45.299 ;
     RECT  40.2 42.803 40.512 45.541 ;
     RECT  4.752 44.867 5.412 45.683 ;
     RECT  40.08 45.541 40.512 45.781 ;
     RECT  24 43.285 25.176 45.829 ;
     RECT  26.7 44.915 27.624 45.829 ;
     RECT  24 45.829 27.624 46.069 ;
     RECT  34.8 41.651 35.112 46.117 ;
     RECT  32.1 44.483 32.412 46.261 ;
     RECT  42.9 44.341 43.368 46.645 ;
     RECT  21.3 44.963 21.864 46.787 ;
     RECT  23.664 46.069 27.624 46.787 ;
     RECT  32.1 46.261 33.096 46.787 ;
     RECT  10.272 44.099 10.812 47.077 ;
     RECT  21.3 46.787 21.612 47.413 ;
     RECT  5.1 45.683 5.412 47.605 ;
     RECT  39.936 45.781 40.512 47.651 ;
     RECT  24 46.787 27.624 47.701 ;
     RECT  29.4 44.483 29.712 47.701 ;
     RECT  18.6 44.099 18.912 47.845 ;
     RECT  20.736 47.413 21.612 47.845 ;
     RECT  24 47.701 29.712 47.845 ;
     RECT  10.272 47.077 10.92 47.891 ;
     RECT  24 47.845 30.12 47.939 ;
     RECT  37.5 40.643 37.812 48.469 ;
     RECT  26.7 47.939 30.12 48.515 ;
     RECT  24 47.939 25.128 48.659 ;
     RECT  13.2 45.155 13.752 48.661 ;
     RECT  12.672 48.661 13.752 48.707 ;
     RECT  20.736 47.845 21.912 48.899 ;
     RECT  17.616 47.845 18.912 48.995 ;
     RECT  4.56 47.605 5.412 49.043 ;
     RECT  21.3 48.899 21.912 49.043 ;
     RECT  42.768 46.645 43.368 49.235 ;
     RECT  37.5 48.469 38.712 49.331 ;
     RECT  34.8 46.117 35.736 49.571 ;
     RECT  41.568 47.845 41.592 49.619 ;
     RECT  15.9 39.587 16.212 49.717 ;
     RECT  26.7 48.515 27.624 49.861 ;
     RECT  42.768 49.235 43.212 50.195 ;
     RECT  24 48.659 25.08 50.243 ;
     RECT  10.272 47.891 10.812 50.339 ;
     RECT  15.9 49.717 16.632 50.531 ;
     RECT  10.368 50.339 10.812 50.771 ;
     RECT  26.496 49.861 27.624 50.771 ;
     RECT  29.4 48.515 30.12 50.771 ;
     RECT  12.672 48.707 13.512 50.867 ;
     RECT  5.1 49.043 5.412 51.781 ;
     RECT  7.8 45.299 8.112 51.781 ;
     RECT  10.5 50.771 10.812 51.781 ;
     RECT  15.9 50.531 16.212 51.781 ;
     RECT  18.6 48.995 18.912 51.781 ;
     RECT  21.3 49.043 21.612 51.781 ;
     RECT  24 50.243 24.456 51.781 ;
     RECT  26.7 50.771 27.624 51.781 ;
     RECT  29.4 50.771 29.712 51.781 ;
     RECT  32.1 46.787 32.412 51.781 ;
     RECT  34.8 49.571 35.352 51.781 ;
     RECT  37.5 49.331 37.812 51.781 ;
     RECT  40.2 47.651 40.512 51.781 ;
     RECT  42.9 50.195 43.212 51.781 ;
     RECT  45.6 2.151 45.912 51.781 ;
     RECT  13.008 50.867 13.512 51.829 ;
     RECT  14.976 51.781 16.212 51.829 ;
     RECT  17.952 51.781 18.912 51.829 ;
     RECT  40.2 51.781 40.824 51.829 ;
     RECT  2.4 34.019 2.712 51.849 ;
     RECT  7.056 51.781 9.048 51.849 ;
     RECT  14.976 51.829 18.912 51.849 ;
     RECT  25.92 51.781 27.912 51.849 ;
     RECT  48.3 2.151 48.612 51.849 ;
     RECT  2.4 51.849 2.52 51.863 ;
     RECT  5.1 51.781 6.072 51.863 ;
     RECT  7.056 51.849 7.92 51.863 ;
     RECT  14.976 51.849 16.02 51.863 ;
     RECT  16.992 51.849 18.912 51.863 ;
     RECT  20.928 51.781 21.96 51.863 ;
     RECT  28.896 51.781 30.888 51.863 ;
     RECT  31.872 51.781 37.812 51.863 ;
     RECT  39.792 51.829 40.824 51.863 ;
     RECT  41.808 51.781 43.8 51.863 ;
     RECT  44.784 51.781 46.776 51.863 ;
     RECT  48.3 51.849 48.42 51.863 ;
     RECT  7.056 51.863 7.08 53.029 ;
     RECT  20.928 51.863 20.952 53.029 ;
     RECT  22.944 51.781 24.456 53.029 ;
     RECT  39.792 51.863 39.816 53.029 ;
     RECT  22.944 53.029 24.936 53.795 ;
     RECT  7.056 53.029 8.04 53.84 ;
     RECT  10.032 51.781 11.016 53.84 ;
     RECT  13.008 51.829 13.992 53.84 ;
     RECT  16.992 51.863 17.976 53.84 ;
     RECT  19.968 53.029 20.952 53.84 ;
     RECT  22.944 53.795 23.928 53.84 ;
     RECT  25.92 51.849 26.904 53.84 ;
     RECT  29.904 51.863 30.888 53.84 ;
     RECT  32.88 51.863 33.864 53.84 ;
     RECT  35.856 51.863 36.84 53.84 ;
     RECT  38.832 53.029 39.816 53.84 ;
     RECT  41.808 51.863 42.792 53.84 ;
     RECT  45.792 51.863 46.776 53.84 ;
     RECT  13.512 10.789 14.784 11.507 ;
     RECT  14.808 10.789 15.9 11.507 ;
     RECT  8.52 11.221 9.504 13.093 ;
     RECT  9.528 11.221 10.5 13.093 ;
     RECT  8.52 13.235 9.6 19.141 ;
     RECT  11.448 13.333 12.48 13.379 ;
     RECT  11.448 13.379 13.2 13.381 ;
     RECT  11.928 13.381 13.2 16.501 ;
     RECT  6.456 14.101 7.8 16.067 ;
     RECT  16.344 14.197 17.616 14.243 ;
     RECT  16.212 14.243 17.616 15.059 ;
     RECT  10.812 14.339 11.904 16.595 ;
     RECT  16.212 15.059 17.808 16.405 ;
     RECT  7.248 16.067 7.8 16.069 ;
     RECT  10.812 16.595 12.528 17.507 ;
     RECT  10.812 17.507 11.064 17.605 ;
     RECT  16.344 18.275 17.376 19.813 ;
     RECT  5.592 18.757 7.056 19.427 ;
     RECT  13.512 18.803 14.232 19.909 ;
     RECT  8.52 19.141 9.504 20.389 ;
     RECT  3.096 19.333 4.56 22.067 ;
     RECT  5.592 19.427 7.248 19.909 ;
     RECT  11.064 19.765 12.192 20.579 ;
     RECT  12.216 19.765 13.2 20.579 ;
     RECT  6.216 19.909 7.248 21.155 ;
     RECT  24.456 20.197 25.92 20.579 ;
     RECT  11.064 20.579 13.2 20.869 ;
     RECT  16.212 20.579 17.376 23.411 ;
     RECT  11.832 20.869 13.2 21.827 ;
     RECT  5.832 21.155 7.248 21.253 ;
     RECT  8.52 21.203 9.504 22.453 ;
     RECT  5.832 21.253 7.152 23.941 ;
     RECT  18.912 22.595 19.032 23.653 ;
     RECT  8.52 22.979 9.6 25.333 ;
     RECT  29.28 23.363 29.4 24.469 ;
     RECT  2.712 23.411 2.904 24.469 ;
     RECT  16.212 23.411 17.808 23.747 ;
     RECT  25.416 23.653 26.7 23.891 ;
     RECT  16.212 23.747 16.344 24.613 ;
     RECT  21.816 23.941 22.944 26.771 ;
     RECT  22.968 23.941 24 26.771 ;
     RECT  32.412 24.563 32.952 25.861 ;
     RECT  2.712 25.715 2.904 27.205 ;
     RECT  13.512 25.813 14.976 30.181 ;
     RECT  5.88 25.859 6.264 26.147 ;
     RECT  5.64 26.147 6.264 27.157 ;
     RECT  30.504 26.533 31.92 26.579 ;
     RECT  21.816 26.771 21.912 26.773 ;
     RECT  25.608 26.773 26.7 27.781 ;
     RECT  32.412 27.107 33.096 27.925 ;
     RECT  5.688 27.157 6.264 27.205 ;
     RECT  5.688 27.205 6.864 28.451 ;
     RECT  18.912 27.395 19.032 28.453 ;
     RECT  24.504 27.923 25.584 29.411 ;
     RECT  32.412 27.925 33.888 28.933 ;
     RECT  5.688 28.451 7.104 30.181 ;
     RECT  3 28.499 3.288 28.933 ;
     RECT  3 28.933 4.368 29.699 ;
     RECT  32.412 28.933 33.552 29.173 ;
     RECT  33.576 29.219 34.8 31.331 ;
     RECT  37.344 29.267 37.5 30.373 ;
     RECT  24.504 29.411 26.016 30.179 ;
     RECT  31.92 29.651 32.1 30.949 ;
     RECT  8.112 29.699 9.6 30.709 ;
     RECT  32.412 29.795 33.504 31.285 ;
     RECT  24.408 30.179 26.016 31.379 ;
     RECT  5.832 30.181 7.104 31.525 ;
     RECT  19.032 30.323 19.08 31.333 ;
     RECT  13.512 30.419 14.976 31.379 ;
     RECT  8.328 30.709 9.6 31.379 ;
     RECT  30.216 31.093 31.488 31.717 ;
     RECT  33.528 31.331 34.8 31.381 ;
     RECT  8.112 31.379 9.6 31.811 ;
     RECT  13.512 31.379 13.608 31.525 ;
     RECT  15.216 31.379 15.36 32.485 ;
     RECT  24.408 31.379 26.448 31.477 ;
     RECT  33.528 31.381 34.704 31.427 ;
     RECT  33.096 31.427 34.704 31.523 ;
     RECT  24.984 31.477 26.448 31.763 ;
     RECT  33.096 31.523 34.8 32.725 ;
     RECT  5.928 31.525 7.104 32.389 ;
     RECT  30.264 31.717 31.488 32.293 ;
     RECT  8.112 31.811 8.52 32.437 ;
     RECT  2.712 31.955 3 32.245 ;
     RECT  2.712 32.245 4.272 32.917 ;
     RECT  30.456 32.293 31.488 33.155 ;
     RECT  27.912 32.485 29.28 33.107 ;
     RECT  35.88 32.581 36.864 32.771 ;
     RECT  33.096 32.725 34.08 34.451 ;
     RECT  35.88 32.771 37.296 35.077 ;
     RECT  2.712 32.917 3.936 33.589 ;
     RECT  30.456 33.155 31.92 34.883 ;
     RECT  8.112 33.683 8.232 34.693 ;
     RECT  13.512 33.877 14.784 35.461 ;
     RECT  16.488 33.973 18 34.259 ;
     RECT  2.712 34.019 3.936 34.835 ;
     RECT  16.344 34.259 18 35.027 ;
     RECT  4.056 34.355 5.1 36.515 ;
     RECT  25.176 34.357 26.7 34.741 ;
     RECT  33.096 34.451 34.176 37.043 ;
     RECT  25.176 34.741 26.448 35.461 ;
     RECT  2.712 34.835 4.032 36.515 ;
     RECT  16.344 35.027 16.68 35.269 ;
     RECT  35.88 35.077 37.056 35.891 ;
     RECT  6.456 35.363 7.8 36.275 ;
     RECT  13.512 35.461 14.544 38.005 ;
     RECT  25.224 35.461 26.448 35.987 ;
     RECT  8.232 35.845 9.696 36.035 ;
     RECT  35.88 35.891 37.296 38.149 ;
     RECT  16.212 35.987 16.68 37.333 ;
     RECT  21.612 35.987 22.2 37.477 ;
     RECT  25.176 35.987 26.448 38.243 ;
     RECT  21.168 37.091 21.3 38.149 ;
     RECT  22.488 37.477 24 38.243 ;
     RECT  38.28 37.573 39.696 37.667 ;
     RECT  27.144 37.669 28.224 38.435 ;
     RECT  28.248 37.669 29.4 38.581 ;
     RECT  5.592 37.907 5.928 38.149 ;
     RECT  13.512 38.005 14.496 39.109 ;
     RECT  5.592 38.149 6.816 38.819 ;
     RECT  25.176 38.243 26.7 38.725 ;
     RECT  27.012 38.435 28.224 40.835 ;
     RECT  25.656 38.725 26.7 41.075 ;
     RECT  24.456 38.771 25.632 41.075 ;
     RECT  37.812 38.819 37.944 39.589 ;
     RECT  7.68 39.107 7.8 40.405 ;
     RECT  30.456 39.589 31.968 40.499 ;
     RECT  37.812 39.589 39.312 40.693 ;
     RECT  36.312 40.163 37.392 40.643 ;
     RECT  5.592 40.405 6.816 41.075 ;
     RECT  30.456 40.499 30.552 40.549 ;
     RECT  36.312 40.643 37.5 42.229 ;
     RECT  37.812 40.693 38.928 41.795 ;
     RECT  28.248 40.787 29.4 40.835 ;
     RECT  27.012 40.835 29.4 40.981 ;
     RECT  27.012 40.981 28.176 42.803 ;
     RECT  28.2 40.981 29.4 42.709 ;
     RECT  5.592 41.075 5.736 42.133 ;
     RECT  24.456 41.075 26.7 41.941 ;
     RECT  35.112 41.651 36.144 42.371 ;
     RECT  24.456 41.941 25.68 42.419 ;
     RECT  25.704 41.941 26.7 42.419 ;
     RECT  36.408 42.229 37.5 42.371 ;
     RECT  24.456 42.419 26.7 43.285 ;
     RECT  30.792 42.613 32.1 42.757 ;
     RECT  5.736 42.709 6.96 42.851 ;
     RECT  30.888 42.757 32.1 43.139 ;
     RECT  27.012 42.803 28.896 43.621 ;
     RECT  5.592 42.851 6.96 43.379 ;
     RECT  30.648 43.139 32.1 44.099 ;
     RECT  19.32 43.285 20.64 44.053 ;
     RECT  25.176 43.285 26.7 45.829 ;
     RECT  5.412 43.379 6.96 44.341 ;
     RECT  27.816 43.621 28.896 44.483 ;
     RECT  18.912 44.099 20.016 45.155 ;
     RECT  5.412 44.341 6.912 44.963 ;
     RECT  20.04 44.387 21.3 45.155 ;
     RECT  21.612 46.787 21.864 47.845 ;
     RECT  39.936 47.651 40.2 48.469 ;
     RECT  16.212 47.845 17.616 48.995 ;
     RECT  40.512 47.845 41.568 49.619 ;
     RECT  41.592 47.845 42.768 49.619 ;
     RECT  38.712 48.469 40.2 49.331 ;
     RECT  25.08 48.659 25.128 49.861 ;
     RECT  16.212 48.995 16.632 49.717 ;
     RECT  25.08 49.861 26.496 50.243 ;
     RECT  10.272 50.339 10.368 50.771 ;
     RECT  16.212 50.531 16.632 51.781 ;
     RECT  10.272 50.771 10.5 51.781 ;
     RECT  26.496 50.771 26.7 51.781 ;
     RECT  29.712 50.771 30.12 51.781 ;
     RECT  6.072 51.781 7.056 51.815 ;
     RECT  9.048 51.781 10.032 51.801 ;
     RECT  13.512 51.781 14.976 51.815 ;
     RECT  16.212 51.781 17.952 51.829 ;
     RECT  21.96 51.781 22.944 51.815 ;
     RECT  24.456 51.781 25.92 53.029 ;
     RECT  27.912 51.781 28.896 51.801 ;
     RECT  30.888 51.781 31.872 51.815 ;
     RECT  40.824 51.781 41.808 51.815 ;
     RECT  43.8 51.781 44.784 51.815 ;
     RECT  46.776 51.781 48.3 51.863 ;
     RECT  9.096 51.801 10.032 51.849 ;
     RECT  27.96 51.801 28.896 51.815 ;
     RECT  6.12 51.815 7.056 51.863 ;
     RECT  13.512 51.815 14.928 51.829 ;
     RECT  22.008 51.815 22.944 51.863 ;
     RECT  27.96 51.815 28.848 51.849 ;
     RECT  30.888 51.815 31.824 51.863 ;
     RECT  40.872 51.815 41.808 51.863 ;
     RECT  43.848 51.815 44.736 51.863 ;
     RECT  13.992 51.829 14.928 51.863 ;
     RECT  7.92 51.849 8.04 51.863 ;
     RECT  16.02 51.849 16.992 51.863 ;
     RECT  7.08 51.863 8.04 53.029 ;
     RECT  24.936 53.029 25.92 53.747 ;
     RECT  24.984 53.747 25.92 53.76 ;
     RECT  24.984 53.76 25.872 53.795 ;
  END
END dsfd_m2l_vc_84x1__he_c4_svcj
END LIBRARY
